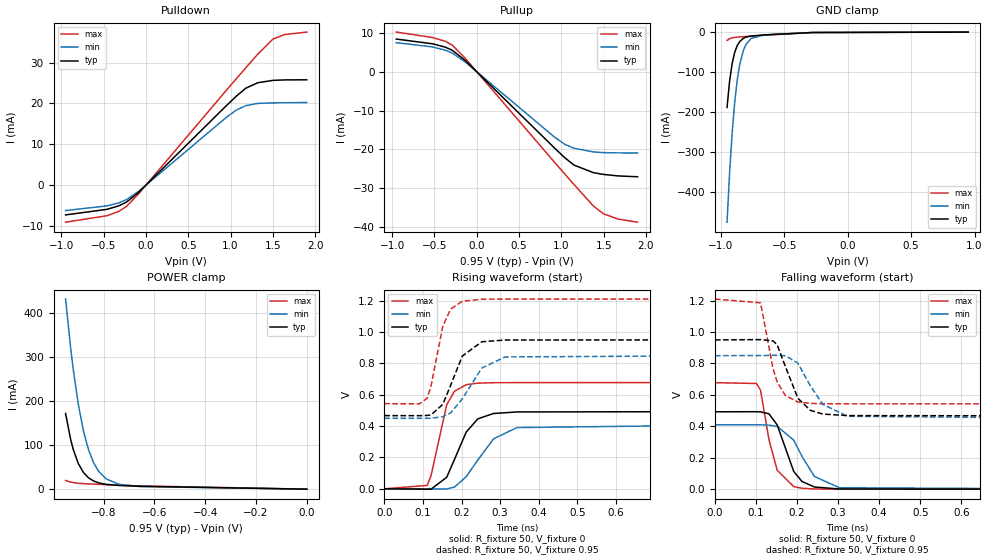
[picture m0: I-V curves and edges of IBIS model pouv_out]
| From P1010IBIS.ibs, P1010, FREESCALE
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[Model] pouv_out
Model_type 3-state
Enable Active-High
Polarity Non-Inverting
Vref=0.95
Vmeas=0.475
C_comp   911fF   857fF   939fF
[Temperature Range] 65   125   -40
[Voltage Range]   0.95   0.85   1.21
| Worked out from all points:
|   slope of the pulldown table from 0 to 0.142 V, typ, clamps not added: 48.1 ohm
|   slope of the pullup table from 0 to 0.142 V, typ, clamps not added: 46.3 ohm
|   GND clamp passes 1 mA (typ) near -0.27 V on its own axis
|   POWER clamp passes 1 mA (typ) near -0.31 V on its own axis
|   falling waveform, R_fixture 50, V_fixture 0: 20-80 % time 42.2ps typ, 54.1ps min, 32.3ps max; typ from 0.493 V to 0 V
|   falling waveform, R_fixture 50, V_fixture 0.95: 20-80 % time 43.8ps typ, 57ps min, 32.2ps max; typ from 0.95 V to 0.467 V
|   rising waveform, R_fixture 50, V_fixture 0: 20-80 % time 54.2ps typ, 73.6ps min, 36.9ps max; typ from 0 V to 0.493 V
|   rising waveform, R_fixture 50, V_fixture 0.95: 20-80 % time 47.9ps typ, 62.9ps min, 34.7ps max; typ from 0.467 V to 0.95 V
[Pullup]
-950mV    8.406mA    7.477mA    10.2mA
-520mV    7.186mA    6.375mA    8.797mA
-370mV    6.311mA    5.543mA    7.815mA
-290mV    5.536mA    4.814mA    6.861mA
-140mV    2.983mA    2.568mA    3.564mA
920mV     -19.65mA   -16.85mA   -23.32mA
1.04V     -22.13mA   -18.67mA   -26.31mA
1.15V     -24.04mA   -19.71mA   -29.04mA
1.38V     -25.99mA   -20.65mA   -34.59mA
1.5V      -26.44mA   -20.83mA   -36.59mA
1.67V     -26.82mA   -20.89mA   -37.93mA
1.9V      -27.04mA   -20.92mA   -38.73mA
[Pulldown]
-950mV    -7.316mA   -6.25mA    -9.099mA
-460mV    -5.947mA   -5.103mA   -7.51mA
-320mV    -5.081mA   -4.352mA   -6.442mA
-230mV    -4.174mA   -3.567mA   -5.229mA
-90mV     -1.842mA   -1.577mA   -2.209mA
950mV     19.45mA    16.59mA    23.22mA
1.07V     21.82mA    18.4mA     26.1mA
1.18V     23.73mA    19.45mA    28.73mA
1.32V     25.06mA    20mA       32.05mA
1.5V      25.64mA    20.13mA    35.76mA
1.64V     25.76mA    20.16mA    36.88mA
1.9V      25.78mA    20.22mA    37.47mA
[GND Clamp]
-950mV    -188.4mA   -475.2mA   -20.78mA
-930mV    -123.3mA   -352.8mA   -16.57mA
-910mV    -79.33mA   -253.5mA   -14.49mA
-890mV    -51.16mA   -176.8mA   -13.36mA
-870mV    -33.84mA   -120.5mA   -12.63mA
-850mV    -23.47mA   -80.94mA   -12.08mA
-820mV    -15.28mA   -44.59mA   -11.36mA
-800mV    -12.49mA   -30.55mA   -10.91mA
-760mV    -9.703mA   -15.9mA    -10.03mA
-660mV    -7.103mA   -6.762mA   -7.877mA
-280mV    -1.114mA   -1.008mA   -930.9uA
950mV     18.39uA    35.88uA    3.979uA
[POWER Clamp]
-950mV    172.2mA    432.7mA    19.91mA
-930mV    112.9mA    321.3mA    16.02mA
-920mV    90.76mA    273.4mA    14.89mA
-900mV    58.49mA    193.5mA    13.47mA
-880mV    38.27mA    133.3mA    12.62mA
-860mV    26.01mA    90.14mA    12mA
-840mV    18.7mA     60.44mA    11.48mA
-820mV    14.37mA    40.7mA     11mA
-790mV    10.89mA    23.34mA    10.31mA
-740mV    8.435mA    11.19mA    9.194mA
-660mV    6.585mA    6.025mA    7.434mA
0V        18.39uA    22.33uA    6.118uA
[Falling Waveform]
R_fixture=50
V_fixture=0
V_fixture_min=0
V_fixture_max=0
0s        492.6mV    409.4mV    677.8mV
101ps     493mV      409.5mV    672.7mV
111.1ps   491.8mV    409.6mV    629.2mV
131.3ps   480.2mV    407.7mV    318.2mV
151.5ps   409.3mV    399.6mV    120.5mV
191.9ps   112.5mV    312mV      16.13mV
212.1ps   48.69mV    208.2mV    5.84mV
242.4ps   13.72mV    80.52mV    1.29mV
303ps     1.124mV    9.222mV    56.62uV
1ns       9.644uV    12.28uV    8.706uV
[Falling Waveform]
R_fixture=50
V_fixture=0.95
V_fixture_min=0.85
V_fixture_max=1.21
0s        950mV      849.9mV    1.21V
111.1ps   951.9mV    850.4mV    1.186V
141.4ps   944.3mV    851.8mV    767.4mV
151.5ps   918.8mV    851.7mV    682.4mV
171.7ps   779.7mV    849.6mV    595.4mV
202ps     578.7mV    801.8mV    555mV
232.3ps   501.9mV    657.9mV    545.9mV
262.6ps   478mV      539.5mV    543.8mV
323.2ps   468.1mV    464mV      543.2mV
1ns       466.8mV    449.5mV    543.2mV
[Rising Waveform]
R_fixture=50
V_fixture=0
V_fixture_min=0
V_fixture_max=0
0s        8.078uV    12.27uV    6.354uV
111.1ps   -2.318mV   -976.2uV   21.52mV
121.2ps   -2.226mV   -1.544mV   84.13mV
161.6ps   73.15mV    -937.6uV   535.9mV
181.8ps   187.3mV    11.04mV    622.5mV
212.1ps   361.8mV    76.9mV     663.7mV
242.4ps   446.4mV    184.2mV    673.9mV
282.8ps   480.2mV    318.2mV    676.6mV
343.4ps   490.1mV    390.5mV    677.2mV
1ns       492.6mV    409.4mV    677.3mV
[Rising Waveform]
R_fixture=50
V_fixture=0.95
V_fixture_min=0.85
V_fixture_max=1.21
0s        466.7mV    449.5mV    542.9mV
90.91ps   466.3mV    449.4mV    541.7mV
111.1ps   467.8mV    449.6mV    577.3mV
121.2ps   471.2mV    450.3mV    657.1mV
151.5ps   538.4mV    459.7mV    1.036V
171.7ps   659.2mV    483.4mV    1.146V
202ps     846.5mV    573.4mV    1.196V
252.5ps   937.7mV    770.4mV    1.209V
313.1ps   948.8mV    841mV      1.21V
1ns       950mV      849.9mV    1.21V
[Ramp]
R_load=50
dV/dt_r   2.956E-1/5.367E-11   2.456E-1/7.332E-11   4.064E-1/3.625E-11
dV/dt_f   2.899E-1/4.331E-11   2.402E-1/5.620E-11   4.001E-1/3.171E-11
| End [Model] pouv_out
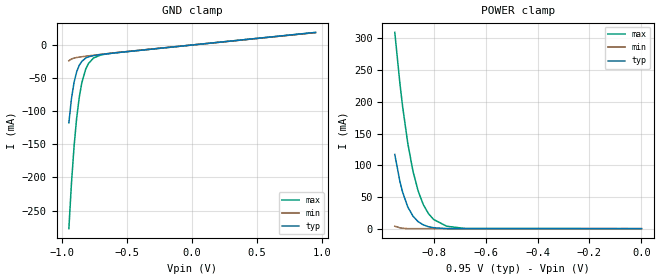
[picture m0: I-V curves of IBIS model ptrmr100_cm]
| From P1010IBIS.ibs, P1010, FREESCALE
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[Model] ptrmr100_cm
Model_type Input
Polarity Non-Inverting
Vinh=0.8
Vinl=0.2
C_comp   861f   858f   865f
[Temperature Range] 65   125   -40
[Voltage Range]   0.95   0.85   1.21
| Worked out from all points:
|   GND clamp passes 1 mA (typ) near -0.05 V on its own axis
|   POWER clamp passes 1 mA (typ) near -0.79 V on its own axis
[GND Clamp]
-950mV    -117.6mA   -23.88mA   -277.3mA
-930mV    -81.21mA   -21.29mA   -209mA
-910mV    -56.51mA   -19.89mA   -153.6mA
-890mV    -40.61mA   -19.02mA   -110.7mA
-870mV    -30.75mA   -18.37mA   -79.18mA
-850mV    -24.75mA   -17.81mA   -56.97mA
-820mV    -19.85mA   -17.05mA   -36.4mA
-800mV    -18.06mA   -16.55mA   -28.36mA
-760mV    -16.04mA   -15.59mA   -19.74mA
-700mV    -14.34mA   -14.19mA   -14.91mA
-600mV    -12.13mA   -11.97mA   -11.98mA
950mV     18.9mA     18.65mA    18.7mA
[POWER Clamp]
-950mV    117mA      3.854mA    309.6mA
-930mV    73.8mA     1.336mA    228mA
-920mV    57.68mA    678.8uA    193.1mA
-900mV    34.27mA    0A         134.7mA
-880mV    19.71mA    0A         90.75mA
-860mV    10.99mA    0A         59.3mA
-840mV    5.915mA    0A         37.75mA
-820mV    3.026mA    0A         23.52mA
-800mV    1.419mA    0A         14.37mA
-750mV    0A         0A         3.804mA
-680mV    0A         0A         301.8uA
0V        0A         0A         0A
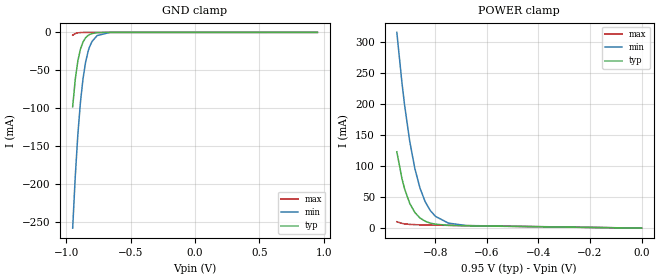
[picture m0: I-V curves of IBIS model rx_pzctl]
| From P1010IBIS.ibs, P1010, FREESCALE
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[Model] rx_pzctl
Model_type Input
Vinh=0.8
Vinl=0.2
C_comp   777.9fF   774fF   777.9fF
[Model Spec]
[Temperature Range] 65   125   -40
[Voltage Range]   0.95   0.85   1.21
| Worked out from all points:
|   GND clamp passes 1 mA (typ) near -0.78 V on its own axis
|   POWER clamp passes 1 mA (typ) near -0.20 V on its own axis
[GND Clamp]
-950mV    -97.94mA   -257.8mA   -3.716mA
-930mV    -61.95mA   -189.9mA   -1.592mA
-910mV    -37.66mA   -134.9mA   -635.2uA
-890mV    -22.19mA   -92.43mA   -240.6uA
-870mV    -12.76mA   -61.31mA   -77.01uA
-850mV    -7.163mA   -39.51mA   0A
-830mV    -3.946mA   -24.87mA   0A
-820mV    -2.931mA   -19.61mA   0A
-800mV    -1.573mA   -12mA      0A
-760mV    -397uA     -4.205mA   0A
-660mV    0A         -40.52uA   0A
950mV     0A         0A         0A
[POWER Clamp]
-950mV    122.8mA    314.9mA    10.28mA
-930mV    79.52mA    233.3mA    7.619mA
-920mV    63.35mA    198.3mA    6.886mA
-900mV    39.84mA    139.8mA    6.034mA
-880mV    25.16mA    95.75mA    5.598mA
-860mV    16.32mA    64.2mA     5.335mA
-840mV    11.12mA    42.55mA    5.144mA
-820mV    8.094mA    28.2mA     4.982mA
-800mV    6.352mA    18.94mA    4.833mA
-750mV    4.532mA    8.087mA    4.476mA
-680mV    3.753mA    4.17mA     3.987mA
0V        69.52nA    46.88nA    142.3nA
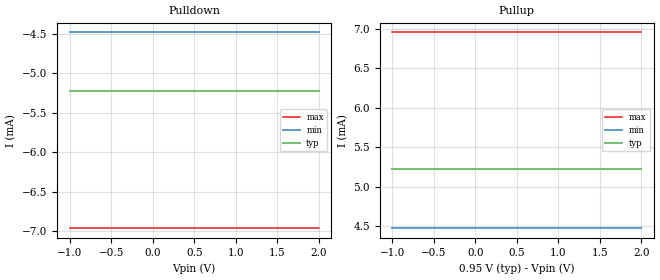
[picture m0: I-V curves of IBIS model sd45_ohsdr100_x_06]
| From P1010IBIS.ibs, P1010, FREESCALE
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[Model] sd45_ohsdr100_x_06
Model_type 3-state
Enable Active-High
Polarity Non-Inverting
|   TYP   MIN   MAX
C_comp   0.00pF   0.00pF   0.00pF
[Model Spec]
Vmeas   0.475   0.425   0.605
[Temperature Range] 65   125   -40
[Voltage Range]   0.95   0.85   1.21
[Pullup]
|   Vout(V)   TYP   WCS   BCS
-1V       5.23mA     4.478mA    6.957mA
2V        5.23mA     4.478mA    6.957mA
[Pulldown]
|   Vout(V)   TYP   WCS   BCS
-1V       -5.229mA   -4.48mA    -6.964mA
2V        -5.229mA   -4.48mA    -6.964mA
[GND Clamp]
|   Vout(V)   TYP   WCS   BCS
-1V       0A         0A         0A
1V        0A         0A         0A
[POWER Clamp]
|   Vout(V)   TYP   WCS   BCS
-1V       0A         0A         0A
0V        0A         0A         0A
[Ramp]
R_load=50
dV/dt_r  2.9887e-01/6.4040e-11  2.6861e-01/6.5155e-11  3.8214e-01/6.5744e-11
dV/dt_f  2.9887e-01/6.6355e-11  2.6861e-01/6.7761e-11  3.8218e-01/6.7348e-11
| End [Model] sd45_ohsdr100_x_06
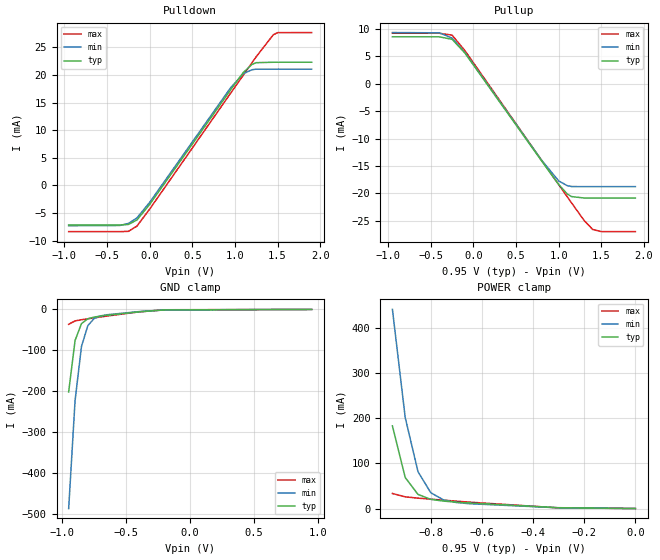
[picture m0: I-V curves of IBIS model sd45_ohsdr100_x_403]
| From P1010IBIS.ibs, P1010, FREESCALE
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[Model] sd45_ohsdr100_x_403
Model_type 3-state
Enable Active-High
Polarity Non-Inverting
|   TYP   MIN   MAX
C_comp   1.60pF   1.60pF   1.67pF
[Model Spec]
Vmeas   0.475   0.425   0.605
[Voltage Range]   0.95   0.85   1.21
[Temperature Range] 65   125   -40
[Driver Schedule]
sd45_ohsdr100_x_40   0ps   NA   0ps   NA
sd45_ohsdr100_x_43   800ps   NA   800ps   NA
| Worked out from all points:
|   slope of the pulldown table from 0 to 0.142 V, typ, clamps not added: 45.7 ohm
|   slope of the pullup table from 0 to 0.142 V, typ, clamps not added: 45.5 ohm
|   GND clamp passes 1 mA (typ) near -0.19 V on its own axis
|   POWER clamp passes 1 mA (typ) near -0.25 V on its own axis
[Pullup]
|   Vout(V)   TYP   WCS   BCS
-950mV    8.533mA    9.319mA    9.19mA
-400mV    8.533mA    9.264mA    9.19mA
-250mV    8.088mA    8.312mA    8.847mA
-100mV    5.595mA    5.69mA     6.03mA
800mV     -14.07mA   -13.94mA   -13.96mA
1V        -18.36mA   -17.7mA    -18.37mA
1.1V      -20.07mA   -18.57mA   -20.58mA
1.15V     -20.56mA   -18.73mA   -21.68mA
1.3V      -20.83mA   -18.75mA   -24.94mA
1.4V      -20.83mA   -18.75mA   -26.56mA
1.5V      -20.83mA   -18.75mA   -26.95mA
1.9V      -20.83mA   -18.75mA   -26.95mA
[Pulldown]
|   Vout(V)   TYP   WCS   BCS
-950mV    -7.174mA   -7.31mA    -8.383mA
-350mV    -7.174mA   -7.267mA   -8.383mA
-250mV    -7.08mA    -6.904mA   -8.331mA
-150mV    -6.282mA   -5.916mA   -7.391mA
0V        -3.456mA   -3.082mA   -4.305mA
950mV     17.31mA    17.69mA    16.7mA
1.1V      20.47mA    20.23mA    20mA
1.2V      21.9mA     20.94mA    22.2mA
1.25V     22.22mA    21.05mA    23.3mA
1.45V     22.3mA     21.05mA    27.27mA
1.5V      22.3mA     21.05mA    27.66mA
1.9V      22.3mA     21.05mA    27.68mA
[GND Clamp]
|   Vout(V)   TYP   WCS   BCS
-950mV    -201.6mA   -486.5mA   -36.16mA
-900mV    -75.75mA   -222.9mA   -28.05mA
-850mV    -34.66mA   -90.59mA   -25.11mA
-800mV    -22.71mA   -39.37mA   -22.78mA
-750mV    -18.57mA   -21.91mA   -20.52mA
-700mV    -16.25mA   -15.71mA   -18.29mA
-650mV    -14.32mA   -12.88mA   -16.07mA
-400mV    -5.858mA   -5.175mA   -5.911mA
-200mV    -1.108mA   -1.072mA   -756.7uA
950mV     70.01uA    122.9uA    16.34uA
[POWER Clamp]
|   Vout(V)   TYP   WCS   BCS
-950mV    183.5mA    442.2mA    33.42mA
-900mV    68.86mA    202.2mA    25.88mA
-850mV    31.34mA    81.75mA    23.04mA
-800mV    20.35mA    35.06mA    20.76mA
-750mV    16.45mA    19.08mA    18.55mA
-700mV    14.21mA    13.35mA    16.36mA
-650mV    12.35mA    10.71mA    14.18mA
-300mV    1.805mA    1.559mA    1.409mA
0V        0A         0A         0A
[Ramp]
R_load=50.00
dV/dt_r  1.9939e-01/6.4174e-11  1.7268e-01/6.5633e-11  2.6621e-01/6.5297e-11
dV/dt_f  1.9939e-01/6.5911e-11  1.7267e-01/6.8201e-11  2.6623e-01/6.6334e-11
| End [Model] sd45_ohsdr100_x_403
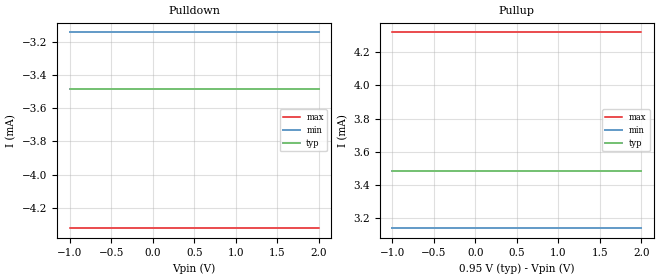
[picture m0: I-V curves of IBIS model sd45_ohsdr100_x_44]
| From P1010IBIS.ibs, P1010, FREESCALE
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[Model] sd45_ohsdr100_x_44
Model_type 3-state
Enable Active-High
Polarity Non-Inverting
|   TYP   MIN   MAX
C_comp   0.00pF   0.00pF   0.00pF
[Model Spec]
Vmeas   0.475   0.425   0.605
[Temperature Range] 65   125   -40
[Voltage Range]   0.95   0.85   1.21
[Pullup]
|   Vout(V)   TYP   WCS   BCS
-1V       3.486mA    3.14mA     4.319mA
2V        3.486mA    3.14mA     4.319mA
[Pulldown]
|   Vout(V)   TYP   WCS   BCS
-1V       -3.486mA   -3.142mA   -4.323mA
2V        -3.486mA   -3.142mA   -4.323mA
[GND Clamp]
|   Vout(V)   TYP   WCS   BCS
-1V       0A         0A         0A
1V        0A         0A         0A
[POWER Clamp]
|   Vout(V)   TYP   WCS   BCS
-1V       0A         0A         0A
0V        0A         0A         0A
[Ramp]
R_load=50
dV/dt_r  1.9939e-01/6.4174e-11  1.7268e-01/6.5633e-11  2.6621e-01/6.5297e-11
dV/dt_f  1.9939e-01/6.5911e-11  1.7267e-01/6.8201e-11  2.6623e-01/6.6334e-11
| End [Model] sd45_ohsdr100_x_44
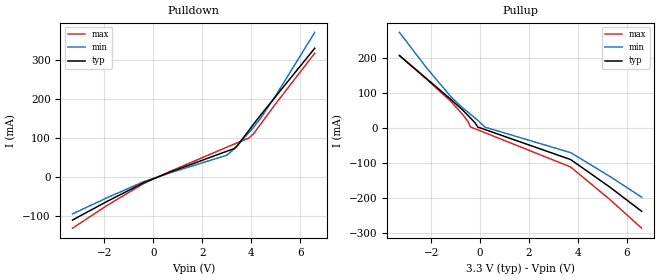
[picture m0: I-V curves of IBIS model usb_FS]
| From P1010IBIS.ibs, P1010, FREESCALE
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[Model] usb_FS
Model_type   I/O
Vinl = 0.8
Vinh = 2
Vmeas = 0.95
Cref = 5E-11
Rref = 50
Vref = 0
| C_comp   typ   min   max
C_comp  9.11p   8.97p   9.24p
| variable   typ   min   max
[Temperature Range]   27.0   -40.0   125.0
| variable   typ   min   max
[Pullup Reference]   3.300V   3.00V   3.6V
| variable   typ   min   max
[Pulldown Reference]   0.000V   0.000V   0.000V
| variable   typ   min   max
[POWER_Clamp_Reference]   3.300V   3.0V   3.60V
| variable   typ   min   max
[GND_Clamp_Reference]   0.000V   0.000V   0.000V
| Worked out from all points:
|   slope of the pulldown table from 0 to 0.495 V, typ, clamps not added: 40.3 ohm
|   slope of the pullup table from 0 to 0.495 V, typ, clamps not added: 41.6 ohm
[Pulldown]
|Voltage   I(typ)   I(min)   I(max)
-3.3V     -110mA     -94.26mA   -130.8mA
-1.9V     -62.61mA   -53.2mA    -73.19mA
-400mV    -14.67mA   -11.84mA   -16.47mA
700mV     13.22mA    11.37mA    14.87mA
3V        66.17mA    55.93mA    76.59mA
3.3V      72.85mA    71.79mA    84.34mA
3.4V      77.81mA    78.37mA    86.91mA
3.9V      119mA      113.6mA    99.99mA
4.1V      135.8mA    127.4mA    111.1mA
4.4V      159.9mA    151.9mA    136.9mA
5V        206.6mA    208.5mA    187.8mA
6.6V      330.4mA    371mA      317.7mA
[Pullup]
|Voltage   I(typ)   I(min)   I(max)
-3.3V     206.2mA    271.9mA    205.5mA
-2.2V     140.9mA    171.8mA    139.2mA
-1.2V     81.43mA    89.19mA    75.68mA
-700mV    50mA       56.08mA    36.82mA
-500mV    35.94mA    45.08mA    18.55mA
-400mV    28.53mA    39.38mA    2.963mA
-200mV    13.96mA    27.66mA    -2.595mA
-100mV    2.572mA    21.77mA    -5.373mA
200mV     -4.636mA   2.225mA    -13.7mA
3.7V      -89.96mA   -70.28mA   -111.2mA
5.3V      -168.3mA   -137.8mA   -203.5mA
6.6V      -237.1mA   -196.9mA   -285mA
[GND_clamp]
0V        0A         0A         0A
100mV     0A         0A         0A
[POWER_clamp]
0V        0A         0A         0A
100mV     0A         0A         0A
[Ramp]
| variable   typ   min   max
dV/dt_r   1.95/4.283n   2.11/3.501n   1.75/5.180n
dV/dt_f   1.95/4.630n   2.11/4.002n   1.75/5.416n
| End [Model] usb_FS
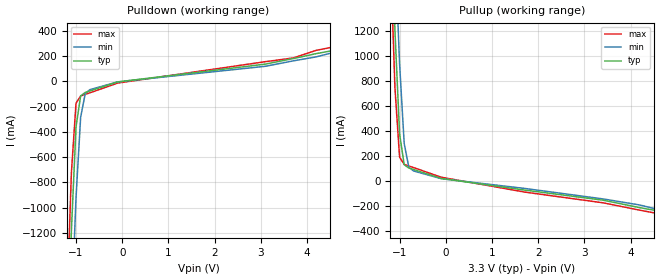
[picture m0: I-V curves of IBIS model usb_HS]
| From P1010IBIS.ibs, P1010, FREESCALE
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[Model] usb_HS
Model_type   I/O
Vinl = 10m
Vinh = 400m
Vmeas = 150m
Cref = 5E-12
Rref = 50
| C_comp   typ   min   max
C_comp  7.19p   6.53p   7.96p
| variable   typ   min   max
[Temperature Range]   27.0   -40.0   125.0
| variable   typ   min   max
[Pullup Reference]   3.300V   3.00V   3.6V
| variable   typ   min   max
[Pulldown Reference]   0.000V   0.000V   0.000V
| variable   typ   min   max
[POWER_Clamp_Reference]   3.300V   3.0V   3.60V
| variable   typ   min   max
[GND_Clamp_Reference]   0.000V   0.000V   0.000V
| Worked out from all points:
|   slope of the pulldown table from 0 to 0.495 V, typ, clamps not added: 22.5 ohm
|   slope of the pullup table from 0 to 0.495 V, typ, clamps not added: 22.5 ohm
[Pulldown]
|Voltage   I(typ)   I(min)   I(max)
-3.3V     -25.44A    -23.8A     -26.86A
-1.2V     -2.217A    -2.794A    -1.795A
-1.1V     -1.182A    -1.85A     -724mA
-1V       -360.4mA   -920.4mA   -173.3mA
-900mV    -114.5mA   -284mA     -115.6mA
-800mV    -87.65mA   -96.06mA   -102.9mA
-700mV    -76.37mA   -65.76mA   -90.71mA
-100mV    -4.452mA   -3.942mA   -13.7mA
3.1V      136.7mA    119.6mA    156mA
3.7V      180.6mA    162.3mA    185.5mA
4.2V      220mA      194.3mA    245.9mA
6.6V      381.4mA    416.5mA    417.8mA
[Pullup]
|Voltage   I(typ)   I(min)   I(max)
-3.3V     25.46A     23.82A     26.88A
-1.2V     2.235A     2.811A     1.814A
-1.1V     1.2A       1.867A     743.6mA
-1V       378.7mA    937.4mA    192.9mA
-900mV    132.9mA    301.1mA    135.2mA
-800mV    106mA      113.3mA    122.4mA
-700mV    94.76mA    82.99mA    110.2mA
-100mV    22.82mA    21.15mA    32.78mA
1.7V      -69.5mA    -56.47mA   -85.53mA
3.4V      -150.7mA   -140.4mA   -171.4mA
4.2V      -210.5mA   -189.2mA   -230.6mA
6.6V      -366.3mA   -407.6mA   -396.8mA
[GND_clamp]
0V        0A         0A         0A
100mV     0A         0A         0A
[POWER_clamp]
0V        0A         0A         0A
100mV     0A         0A         0A
[Ramp]
| variable   typ   min   max
dV/dt_r   0.24/880.963p   0.22/532.484p   0.26/1.108n
dV/dt_f   0.24/431.881p   0.22/372.480p   0.26/513.903p
| End [Model] usb_HS
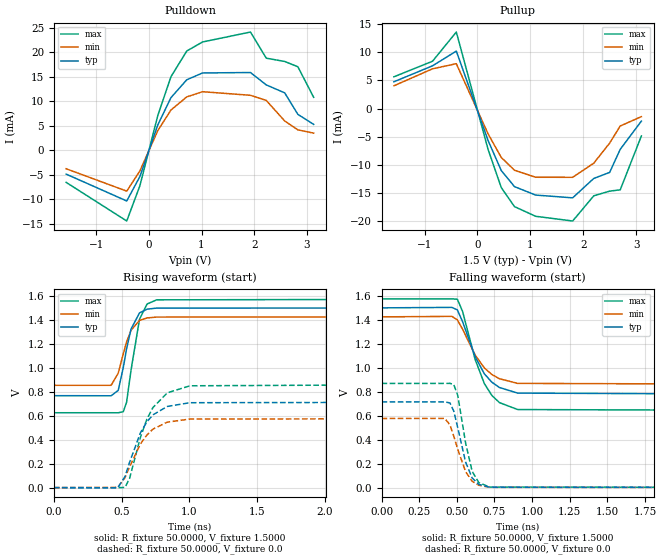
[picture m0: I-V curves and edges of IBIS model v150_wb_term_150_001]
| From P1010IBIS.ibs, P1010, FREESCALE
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[Model] v150_wb_term_150_001
|   Model v150_wb_term_150_001
| This model was characterised for following simulation conditions:
| External (pad) voltage:
|   - Typ: 1.5V,   - Min: 1.425V,   - Max: 1.575V
| Library cells for typ/min/max conditions are connected as defined below:
|  chip_pad - External Pad
|  ipp_do - Core Input
|  ipp_obe - Output Buffer Enable
|  esd_boost - vdd_io
|  gnd_io - gnd_io
|  vdd_d - vdd_d
|  vdd_io - vdd_io
|  vipp_dse_0 - gnd_io
|  vipp_dse_1 - vdd_d vdd_d gnd_io
|  vipp_dse_2 - vdd_d gnd_io gnd_io
|  vipp_dse_3 - gnd_io
|  vipp_dse_4 - gnd_io
|  vipp_dse_5 - vdd_d vdd_d gnd_io
|  vipp_dse_6 - vdd_d gnd_io vdd_d
|  vipp_dse_7 - gnd_io gnd_io vdd_d
|  vsel[0] - gnd_io
|  vsel[1] - vdd_d
|  vtermsel_0 - gnd_io
|  vtermsel_1 - gnd_io
|  vtermsel_2 - vdd_d
| All other pins connected to ground
Model_type I/O
Polarity   Non-Inverting
Enable   Active-High
Vinl =   0.5750V
Vinh =   0.9250V
Vmeas =  0.7500V
Cref =   0.0F
Rref =   50.0000
Vref =   0.7500V
C_comp   2.2026pF   1.9235pF   2.5884pF
[Receiver Thresholds]
Vth   =  0.750V
Vinh_ac  =  0.175V
Vinh_dc  =  0.100V
Vinl_ac  = -0.175V
Vinl_dc  = -0.100V
[Temperature Range]   65.0000   0.1250k   -40.0000
[Voltage Range]   1.5000V   1.4250V   1.5750V
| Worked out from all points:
|   slope of the pulldown table from 0 to 0.225 V, typ, clamps not added: 35.6 ohm
|   slope of the pullup table from 0 to 0.225 V, typ, clamps not added: 36 ohm
|   rising waveform, R_fixture 50.0000, V_fixture 1.5000: 20-80 % time 80.4ps typ, 90.1ps min, 77.1ps max; typ from 0.768 V to 1.5 V
|   rising waveform, R_fixture 50.0000, V_fixture 0.0: 20-80 % time 162ps typ, 168ps min, 166ps max; typ from 0 V to 0.716 V
|   falling waveform, R_fixture 50.0000, V_fixture 1.5000: 20-80 % time 159ps typ, 167ps min, 148ps max; typ from 1.5 V to 0.768 V
|   falling waveform, R_fixture 50.0000, V_fixture 0.0: 20-80 % time 84.1ps typ, 94.3ps min, 75.4ps max; typ from 0.716 V to 0 V
[Pulldown]
|Voltage   I(typ)   I(min)   I(max)
-1.57V    -4.914mA   -3.818mA   -6.602mA
-420mV    -10.4mA    -8.389mA   -14.49mA
-170mV    -5.399mA   -4.253mA   -7.279mA
170mV     5.137mA    3.982mA    7.064mA
420mV     10.71mA    8.187mA    14.99mA
720mV     14.36mA    10.86mA    20.23mA
1.02V     15.75mA    11.92mA    22.08mA
1.93V     15.84mA    11.19mA    24.11mA
2.23V     13.31mA    10.14mA    18.77mA
2.58V     11.69mA    5.94mA     18.1mA
2.83V     7.3mA      4.13mA     17.02mA
3.13V     5.25mA     3.46mA     10.78mA
[Pullup]
|Voltage   I(typ)   I(min)   I(max)
-1.58V    4.77mA     4.06mA     5.65mA
-850mV    7.598mA    7.066mA    8.413mA
-400mV    10.21mA    7.977mA    13.59mA
200mV     -5.632mA   -4.457mA   -7.203mA
450mV     -10.97mA   -8.649mA   -13.99mA
700mV     -13.82mA   -10.92mA   -17.37mA
1.1V      -15.32mA   -12.16mA   -19.08mA
1.8V      -15.81mA   -12.17mA   -19.92mA
2.2V      -12.37mA   -9.661mA   -15.45mA
2.5V      -11.3mA    -6.103mA   -14.62mA
2.7V      -7.204mA   -3.069mA   -14.39mA
3.1V      -2.206mA   -1.416mA   -4.843mA
[Ramp]
| variable   typ   min   max
dV/dt_r  0.4296/0.1623n   0.3469/0.1685n   0.5223/0.1664n
dV/dt_f  0.4395/0.1589n   0.3427/0.1667n   0.5638/0.1475n
R_load = 50.0000
[Rising Waveform]
R_fixture= 50.0000
V_fixture= 1.5000
V_fixture_min= 1.4250
V_fixture_max= 1.5750
|time   V(typ)   V(min)   V(max)
0s        767.5mV    853.8mV    624.9mV
422.9ps   766.6mV    853.9mV    624.9mV
475.2ps   811.8mV    955.6mV    624.7mV
512.3ps   1.002V     1.116V     633.6mV
536.5ps   1.157V     1.215V     711.5mV
569.9ps   1.324V     1.314V     981.7mV
632.2ps   1.458V     1.395V     1.405V
687.9ps   1.489V     1.416V     1.532V
758.8ps   1.498V     1.423V     1.567V
5ns       1.5V       1.425V     1.575V
[Rising Waveform]
R_fixture= 50.0000
V_fixture= 0.0
V_fixture_min= 0.0
V_fixture_max= 0.0
|time   V(typ)   V(min)   V(max)
0s        7.324uV    39.66uV    145.1nV
471.2ps   -1.643mV   2.083mV    195.1uV
525.2ps   92.5mV     84.61mV    1.477mV
558.8ps   211.3mV    173.3mV    77.35mV
638.4ps   456mV      363.6mV    418.5mV
686.5ps   549.4mV    439.5mV    571.3mV
731ps     607.3mV    488.1mV    668.2mV
837.4ps   677.6mV    546.8mV    791.1mV
1.004ns   708.6mV    572.3mV    849.8mV
5ns       716.1mV    578.2mV    870.5mV
[Falling Waveform]
R_fixture= 50.0000
V_fixture= 1.5000
V_fixture_min= 1.4250
V_fixture_max= 1.5750
|time   V(typ)   V(min)   V(max)
0s        1.5V       1.425V     1.575V
466.9ps   1.504V     1.429V     1.575V
503.3ps   1.483V     1.4V       1.572V
538.1ps   1.385V     1.322V     1.47V
621.4ps   1.093V     1.107V     1.07V
683ps     949.7mV    998.9mV    867.9mV
732.8ps   880.2mV    944.3mV    769.6mV
782.9ps   836.2mV    909.3mV    710.4mV
903.8ps   789.6mV    870.6mV    652.6mV
5ns       767.5mV    853.8mV    635.4mV
[Falling Waveform]
R_fixture= 50.0000
V_fixture= 0.0
V_fixture_min= 0.0
V_fixture_max= 0.0
|time   V(typ)   V(min)   V(max)
0s        716.1mV    578.2mV    870.5mV
419.9ps   716.4mV    578.4mV    870.5mV
454.3ps   707.4mV    524.5mV    870.9mV
478.9ps   641.5mV    433.7mV    862.2mV
505.9ps   502.1mV    321.6mV    771mV
557.8ps   216.3mV    135.4mV    376.2mV
601.5ps   82.45mV    55.39mV    137.9mV
645.9ps   28.67mV    21.31mV    43.71mV
716.5ps   5.495mV    4.642mV    6.886mV
5ns       7.524uV    40.13uV    220.6nV
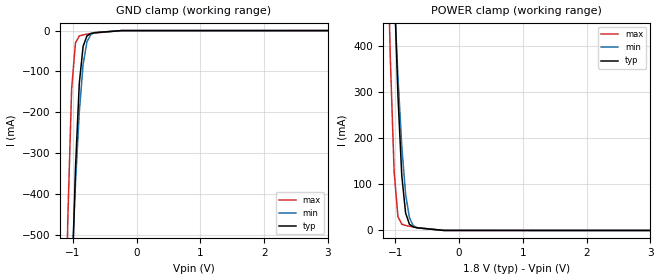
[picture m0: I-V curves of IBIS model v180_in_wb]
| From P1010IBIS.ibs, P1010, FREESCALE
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[Model] v180_in_wb
|   Model v180_in_wb
| This model has derived from v180_wb
| Only applicable curves and parameters are copied
Model_type Input
Polarity   Non-Inverting
Enable   Active-High
Vinl =   0.5400V
Vinh =   1.2600V
C_comp   2.1221pF   1.9600pF   2.4667pF
[Temperature Range]   85.0000   0.1250k   -40.0000
[Voltage Range]   1.8000V   1.6200V   1.9800V
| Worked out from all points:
|   GND clamp passes 1 mA (typ) near -0.40 V on its own axis
|   POWER clamp passes 1 mA (typ) near -0.37 V on its own axis
[GND_clamp]
|Voltage   I(typ)   I(min)   I(max)
-1.98V    -8.37A     -5.087A    -9.647A
-1.14V    -1.459A    -1.082A    -930.9mA
-1.08V    -1.036A    -828.3mA   -462.6mA
-1.02V    -653.4mA   -590.2mA   -143.2mA
-960mV    -338mA     -376mA     -30.24mA
-900mV    -129.6mA   -200.5mA   -13.2mA
-840mV    -38.64mA   -82.98mA   -10.47mA
-780mV    -13.16mA   -27.75mA   -8.896mA
-720mV    -7.156mA   -9.942mA   -7.424mA
-660mV    -5.182mA   -5.042mA   -5.995mA
-240mV    -56.29uA   -39.98uA   -23.22uA
3.9V      0A         0A         0A
[POWER_clamp]
|Voltage   I(typ)   I(min)   I(max)
-1.92V    6.087A     4.039A     6.601A
-1.14V    1.168A     928.8mA    722.7mA
-1.08V    840.5mA    715.6mA    374.8mA
-1.02V    542mA      514.8mA    127.3mA
-960mV    291.6mA    333.1mA    29.94mA
-900mV    119mA      182.4mA    13.62mA
-840mV    37.87mA    78.7mA     10.87mA
-780mV    13.54mA    27.69mA    9.257mA
-720mV    7.641mA    10.53mA    7.748mA
-660mV    5.688mA    5.717mA    6.285mA
-240mV    130.6uA    144.5uA    23.85uA
3.96V     0A         0A         0A
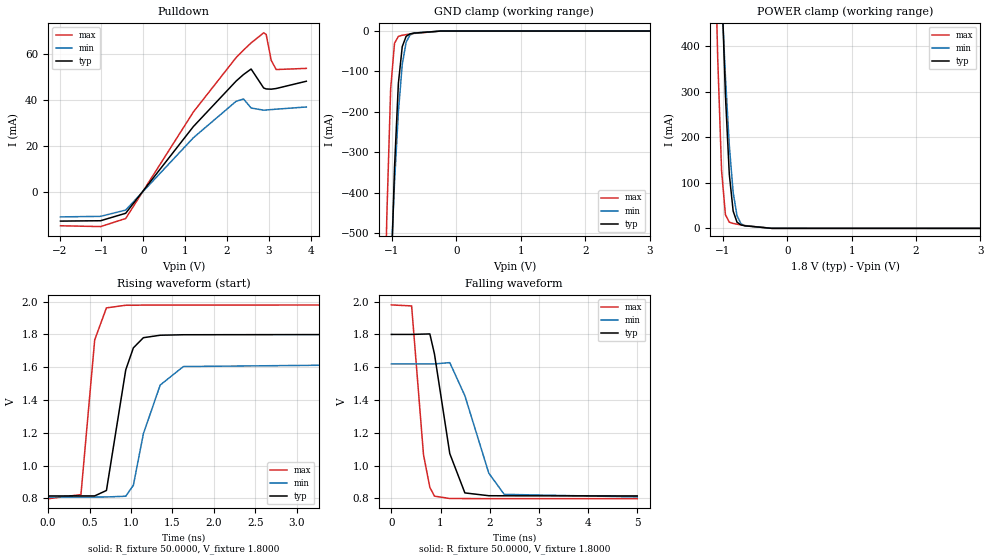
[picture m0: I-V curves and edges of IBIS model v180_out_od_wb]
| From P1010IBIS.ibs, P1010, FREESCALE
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[Model] v180_out_od_wb
|   Model v180_out_od_wb
| This model has derived from v180_wb
| Only applicable curves and parameters are copied
Model_type Open_drain
Polarity   Non-Inverting
Enable   Active-High
Vmeas =  0.9000V
Cref =   0.0F
Rref =   50.0000
Vref =   0.9000V
C_comp   2.1221pF   1.9600pF   2.4667pF
[Temperature Range]   85.0000   0.1250k   -40.0000
[Voltage Range]   1.8000V   1.6200V   1.9800V
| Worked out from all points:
|   slope of the pulldown table from 0 to 0.27 V, typ, clamps not added: 40.4 ohm
|   GND clamp passes 1 mA (typ) near -0.40 V on its own axis
|   POWER clamp passes 1 mA (typ) near -0.37 V on its own axis
|   rising waveform, R_fixture 50.0000, V_fixture 1.8000: 20-80 % time 186ps typ, 252ps min, 118ps max; typ from 0.814 V to 1.8 V
|   falling waveform, R_fixture 50.0000, V_fixture 1.8000: 20-80 % time 320ps typ, 504ps min, 177ps max; typ from 1.8 V to 0.814 V
[Pulldown]
|Voltage   I(typ)   I(min)   I(max)
-1.98V    -12.66mA   -10.83mA   -14.68mA
-1.02V    -12.5mA    -10.6mA    -15.04mA
-420mV    -9.259mA   -7.874mA   -11.53mA
1.2V      28.39mA    23.53mA    34.72mA
2.22V     48.08mA    39.31mA    58.26mA
2.4V      50.97mA    40.32mA    61.59mA
2.58V     53.33mA    36.41mA    64.65mA
2.88V     45.1mA     35.47mA    69.04mA
2.94V     44.69mA    35.54mA    68.34mA
3.06V     44.58mA    35.73mA    57.1mA
3.18V     44.88mA    35.91mA    53.1mA
3.9V      48.03mA    36.86mA    53.61mA
[GND_clamp]
|Voltage   I(typ)   I(min)   I(max)
-1.98V    -8.37A     -5.087A    -9.647A
-1.14V    -1.459A    -1.082A    -930.9mA
-1.08V    -1.036A    -828.3mA   -462.6mA
-1.02V    -653.4mA   -590.2mA   -143.2mA
-960mV    -338mA     -376mA     -30.24mA
-900mV    -129.6mA   -200.5mA   -13.2mA
-840mV    -38.64mA   -82.98mA   -10.47mA
-780mV    -13.16mA   -27.75mA   -8.896mA
-720mV    -7.156mA   -9.942mA   -7.424mA
-660mV    -5.182mA   -5.042mA   -5.995mA
-240mV    -56.29uA   -39.98uA   -23.22uA
3.9V      0A         0A         0A
[POWER_clamp]
|Voltage   I(typ)   I(min)   I(max)
-1.92V    6.087A     4.039A     6.601A
-1.14V    1.168A     928.8mA    722.7mA
-1.08V    840.5mA    715.6mA    374.8mA
-1.02V    542mA      514.8mA    127.3mA
-960mV    291.6mA    333.1mA    29.94mA
-900mV    119mA      182.4mA    13.62mA
-840mV    37.87mA    78.7mA     10.87mA
-780mV    13.54mA    27.69mA    9.257mA
-720mV    7.641mA    10.53mA    7.748mA
-660mV    5.688mA    5.717mA    6.285mA
-240mV    130.6uA    144.5uA    23.85uA
3.96V     0A         0A         0A
[Ramp]
| variable   typ   min   max
dV/dt_r  0.5852/0.3523n   0.4766/0.5910n   0.7103/0.1825n
dV/dt_f  0.5912/0.3203n   0.4869/0.5037n   0.7093/0.1774n
R_load = 50.0000
[Rising Waveform]
R_fixture= 50.0000
V_fixture= 1.8000
V_fixture_min= 1.6200
V_fixture_max= 1.9800
|time   V(typ)   V(min)   V(max)
0s        814.3mV    807.8mV    797.5mV
396ps     814.4mV    807.8mV    822.5mV
562.2ps   814.6mV    807.9mV    1.767V
703.9ps   847.6mV    808.1mV    1.962V
937.1ps   1.584V     812.5mV    1.978V
1.029ns   1.718V     879.5mV    1.978V
1.15ns    1.78V      1.194V     1.979V
1.353ns   1.795V     1.491V     1.979V
1.633ns   1.798V     1.604V     1.979V
5ns       1.8V       1.62V      1.98V
[Falling Waveform]
R_fixture= 50.0000
V_fixture= 1.8000
V_fixture_min= 1.6200
V_fixture_max= 1.9800
|time   V(typ)   V(min)   V(max)
0s        1.8V       1.62V      1.98V
412.1ps   1.8V       1.62V      1.974V
653.6ps   1.802V     1.62V      1.066V
782.7ps   1.803V     1.62V      866.8mV
876.4ps   1.681V     1.62V      813.2mV
1.188ns   1.073V     1.628V     798.8mV
1.495ns   832.9mV    1.426V     798.3mV
1.981ns   815.8mV    953.9mV    797.9mV
2.294ns   815.3mV    824.2mV    797.7mV
5ns       814.5mV    808.3mV    797.6mV
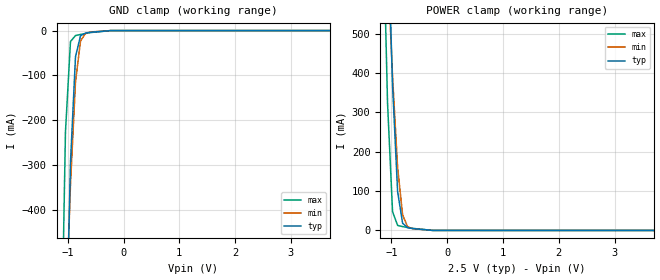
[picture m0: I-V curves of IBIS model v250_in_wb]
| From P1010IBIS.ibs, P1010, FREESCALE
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[Model] v250_in_wb
|   Model v250_in_wb
| This model has derived from v250_wb
| Only applicable curves and parameters are copied
Model_type Input
Polarity   Non-Inverting
Enable   Active-High
Vinl =   0.7500V
Vinh =   1.7500V
C_comp   2.1221pF   1.9600pF   2.4667pF
[Temperature Range]   85.0000   0.1250k   -40.0000
[Voltage Range]   2.5000V   2.2500V   2.7500V
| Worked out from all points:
|   GND clamp passes 1 mA (typ) near -0.40 V on its own axis
|   POWER clamp passes 1 mA (typ) near -0.37 V on its own axis
[GND_clamp]
|Voltage   I(typ)   I(min)   I(max)
-2.75V    -14.95A    -8.916A    -17.97A
-1.13V    -1.387A    -1.039A    -846.5mA
-1.04V    -775.3mA   -667.5mA   -226.6mA
-950mV    -294.9mA   -343.6mA   -24.45mA
-860mV    -58.51mA   -114.8mA   -11.13mA
-770mV    -11.55mA   -23.09mA   -8.664mA
-680mV    -5.737mA   -6.117mA   -6.48mA
-590mV    -3.79mA    -3.141mA   -4.402mA
-230mV    -44.51uA   -32.23uA   -16.96uA
5.44V     0A         0A         0A
[POWER_clamp]
|Voltage   I(typ)   I(min)   I(max)
-2.69V    11.16A     7.25A      12.69A
-1.16V    1.281A     1.002A     850.9mA
-1.07V    788.5mA    681.3mA    324.6mA
-980mV    368.1mA    391mA      47.84mA
-890mV    99.61mA    161.5mA    12.91mA
-800mV    18.31mA    39.69mA    9.783mA
-710mV    7.241mA    9.319mA    7.51mA
-620mV    4.876mA    4.494mA    5.346mA
-260mV    201.3uA    213.5uA    41.93uA
5.5V      0A         0A         0A
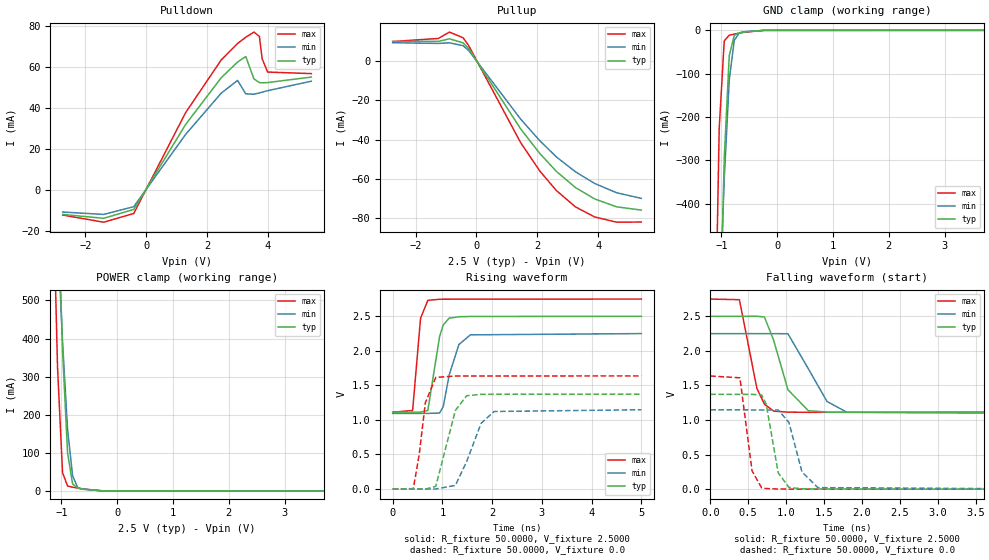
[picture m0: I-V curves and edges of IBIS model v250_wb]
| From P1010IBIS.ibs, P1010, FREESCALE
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[Model] v250_wb
|   Model v250_wb
| This model was characterised for following simulation conditions:
| External (pad) voltage:
|   - Typ: 2.5V,   - Min: 2.25V,   - Max: 2.75V
| Library cells for typ/min/max conditions are connected as defined below:
|  chip_pad - External Pad
|  ipp_do - Core Input
|  ipp_obe - Output Buffer Enable
|  esd_boost - vdd_io
|  gnd_io - gnd_io
|  nbias - nbias
|  nbias_bot - nbias_bot
|  nbias_dc - nbias_dc
|  nbias_top - nbias_top
|  pbias - pbias
|  pbias_bot - pbias_bot
|  pbias_dc - pbias_dc
|  pbias_top - pbias_top
|  v12 - v12
|  v12_dc - v12_dc
|  v12_top - v12_top
|  vdd_d - vdd_d
|  vdd_io - vdd_io
|  vsel[2] - gnd_io
|  vsel[3] - vdd_d
|  vsel[4] - gnd_io
| All other pins connected to ground
Model_type I/O
Polarity   Non-Inverting
Enable   Active-High
Vinl =   0.7500V
Vinh =   1.7500V
Vmeas =  1.2500V
Cref =   0.0F
Rref =   50.0000
Vref =   1.2500V
C_comp   2.1221pF   1.9600pF   2.4667pF
[Temperature Range]   85.0000   0.1250k   -40.0000
[Voltage Range]   2.5000V   2.2500V   2.7500V
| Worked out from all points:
|   slope of the pulldown table from 0 to 0.375 V, typ, clamps not added: 38.9 ohm
|   slope of the pullup table from 0 to 0.375 V, typ, clamps not added: 39.9 ohm
|   GND clamp passes 1 mA (typ) near -0.40 V on its own axis
|   POWER clamp passes 1 mA (typ) near -0.37 V on its own axis
|   rising waveform, R_fixture 50.0000, V_fixture 2.5000: 20-80 % time 180ps typ, 235ps min, 112ps max; typ from 1.11 V to 2.5 V
|   rising waveform, R_fixture 50.0000, V_fixture 0.0: 20-80 % time 275ps typ, 371ps min, 177ps max; typ from 0 V to 1.37 V
|   falling waveform, R_fixture 50.0000, V_fixture 2.5000: 20-80 % time 234ps typ, 336ps min, 160ps max; typ from 2.5 V to 1.11 V
|   falling waveform, R_fixture 50.0000, V_fixture 0.0: 20-80 % time 127ps typ, 169ps min, 96.5ps max; typ from 1.37 V to 0 V
[Pulldown]
|Voltage   I(typ)   I(min)   I(max)
-2.75V    -11.96mA   -10.79mA   -12.27mA
-1.4V     -13.85mA   -11.95mA   -15.75mA
-410mV    -9.504mA   -8.167mA   -11.5mA
1.3V      32.04mA    27.19mA    37.83mA
2.47V     54.84mA    47.31mA    63.54mA
3.01V     62.54mA    53.57mA    71.61mA
3.28V     65.25mA    47.01mA    74.69mA
3.55V     54.3mA     46.83mA    77.2mA
3.73V     52.51mA    47.45mA    75.09mA
3.82V     52.38mA    47.81mA    64.2mA
4V        52.52mA    48.55mA    57.65mA
5.44V     55.2mA     53.18mA    56.9mA
[Pullup]
|Voltage   I(typ)   I(min)   I(max)
-2.75V    9.9mA      9.29mA     9.9mA
-1.25V    9.96mA     8.92mA     11.45mA
-890mV    11.28mA    9.24mA     14.69mA
-440mV    9.214mA    7.771mA    11.81mA
-260mV    6.366mA    5.376mA    7.908mA
1.45V     -34.57mA   -29.59mA   -41.58mA
2.08V     -47.11mA   -40.62mA   -56.03mA
2.62V     -56.14mA   -48.79mA   -65.9mA
3.25V     -64.44mA   -56.41mA   -74.27mA
3.88V     -70.19mA   -62.34mA   -79.38mA
4.6V      -74.22mA   -67.05mA   -82.03mA
5.41V     -75.87mA   -69.91mA   -81.94mA
[GND_clamp]
|Voltage   I(typ)   I(min)   I(max)
-2.75V    -14.95A    -8.916A    -17.97A
-1.13V    -1.387A    -1.039A    -846.5mA
-1.04V    -775.3mA   -667.5mA   -226.6mA
-950mV    -294.9mA   -343.6mA   -24.45mA
-860mV    -58.51mA   -114.8mA   -11.13mA
-770mV    -11.55mA   -23.09mA   -8.664mA
-680mV    -5.737mA   -6.117mA   -6.48mA
-590mV    -3.79mA    -3.141mA   -4.402mA
-230mV    -44.51uA   -32.23uA   -16.96uA
5.44V     0A         0A         0A
[POWER_clamp]
|Voltage   I(typ)   I(min)   I(max)
-2.69V    11.16A     7.25A      12.69A
-1.16V    1.281A     1.002A     850.9mA
-1.07V    788.5mA    681.3mA    324.6mA
-980mV    368.1mA    391mA      47.84mA
-890mV    99.61mA    161.5mA    12.91mA
-800mV    18.31mA    39.69mA    9.783mA
-710mV    7.241mA    9.319mA    7.51mA
-620mV    4.876mA    4.494mA    5.346mA
-260mV    201.3uA    213.5uA    41.93uA
5.5V      0A         0A         0A
[Ramp]
| variable   typ   min   max
dV/dt_r  0.8231/0.2751n   0.6881/0.3712n   0.9819/0.1767n
dV/dt_f  0.8322/0.2342n   0.6935/0.3357n   0.9831/0.1602n
R_load = 50.0000
[Rising Waveform]
R_fixture= 50.0000
V_fixture= 2.5000
V_fixture_min= 2.2500
V_fixture_max= 2.7500
|time   V(typ)   V(min)   V(max)
0s        1.113V     1.094V     1.111V
400.6ps   1.113V     1.094V     1.137V
560.3ps   1.113V     1.094V     2.472V
706.3ps   1.136V     1.094V     2.732V
943.6ps   2.21V      1.1V       2.747V
1.017ns   2.375V     1.193V     2.748V
1.136ns   2.474V     1.651V     2.748V
1.331ns   2.494V     2.091V     2.749V
1.563ns   2.498V     2.232V     2.749V
5ns       2.5V       2.25V      2.75V
[Rising Waveform]
R_fixture= 50.0000
V_fixture= 0.0
V_fixture_min= 0.0
V_fixture_max= 0.0
|time   V(typ)   V(min)   V(max)
0s        11.46uV    23.25uV    1.779uV
414.3ps   -36.43uV   5.787uV    4.619mV
533.5ps   -83.29uV   -7.474uV   499.9mV
655.9ps   -2.986mV   -23.92uV   1.248V
866.1ps   37.64mV    -431.1uV   1.615V
1.261ns   1.138V     51.92mV    1.636V
1.487ns   1.35V      397.7mV    1.636V
1.777ns   1.37V      949.1mV    1.636V
2.038ns   1.371V     1.122V     1.636V
5ns       1.372V     1.147V     1.637V
[Falling Waveform]
R_fixture= 50.0000
V_fixture= 2.5000
V_fixture_min= 2.2500
V_fixture_max= 2.7500
|time   V(typ)   V(min)   V(max)
0s        2.5V       2.25V      2.75V
384.1ps   2.5V       2.25V      2.741V
614.3ps   2.501V     2.25V      1.459V
713.7ps   2.491V     2.25V      1.23V
834.2ps   2.159V     2.25V      1.13V
1.024ns   1.439V     2.248V     1.114V
1.293ns   1.135V     1.742V     1.112V
1.539ns   1.116V     1.269V     1.112V
1.803ns   1.114V     1.112V     1.112V
5ns       1.113V     1.094V     1.111V
[Falling Waveform]
R_fixture= 50.0000
V_fixture= 0.0
V_fixture_min= 0.0
V_fixture_max= 0.0
|time   V(typ)   V(min)   V(max)
0s        1.372V     1.147V     1.637V
390.9ps   1.371V     1.147V     1.611V
550.8ps   1.371V     1.146V     265.7mV
677.1ps   1.363V     1.146V     19.64mV
737.3ps   1.231V     1.146V     9.081mV
895.4ps   237.2mV    1.146V     2.145mV
1.037ns   25.61mV    965.5mV    1.373mV
1.209ns   5.635mV    249.6mV    860uV
1.418ns   1.605mV    22.47mV    496.2uV
5ns       98.66uV    144.2uV    46.47uV
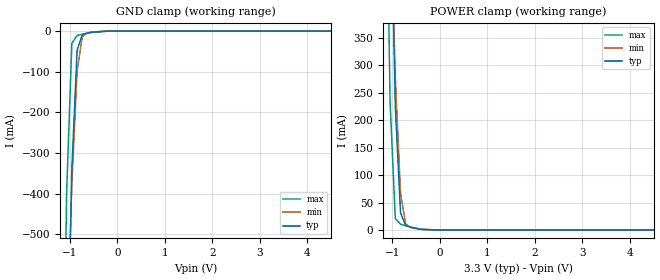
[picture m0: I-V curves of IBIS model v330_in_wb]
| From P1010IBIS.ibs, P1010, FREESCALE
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[Model] v330_in_wb
|   Model v330_in_wb
| This model has derived from v330_wb
| Only applicable curves and parameters are copied
Model_type Input
Polarity   Non-Inverting
Enable   Active-High
Vinl =   0.9900V
Vinh =   2.3100V
C_comp   2.1221pF   1.9600pF   2.4667pF
[Temperature Range]   85.0000   0.1250k   -40.0000
[Voltage Range]   3.3000V   3.0000V   3.6000V
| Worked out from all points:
|   GND clamp passes 1 mA (typ) near -0.40 V on its own axis
|   POWER clamp passes 1 mA (typ) near -0.36 V on its own axis
[GND_clamp]
|Voltage   I(typ)   I(min)   I(max)
-3.6V     -22.25A    -13.16A    -27.15A
-1.18V    -1.756A    -1.257A    -1.286A
-1.07V    -969.3mA   -787.6mA   -396.2mA
-960mV    -338.2mA   -376.1mA   -30.28mA
-850mV    -47.6mA    -98.06mA   -10.8mA
-740mV    -8.434mA   -13.66mA   -7.93mA
-630mV    -4.58mA    -4.071mA   -5.312mA
-520mV    -2.593mA   -2.032mA   -2.91mA
-190mV    -17.06uA   -13.9uA    -5.444uA
7.18V     0A         0A         0A
[POWER_clamp]
|Voltage   I(typ)   I(min)   I(max)
-3.58V    17.06A     10.98A     19.73A
-1.16V    1.281A     1.002A     850.9mA
-1.05V    686.8mA    613.5mA    233.8mA
-940mV    224.1mA    278.8mA    20.58mA
-830mV    31.31mA    66.9mA     10.6mA
-720mV    7.718mA    10.63mA    7.76mA
-610mV    4.705mA    4.29mA     5.119mA
-390mV    1.251mA    1.145mA    864.4uA
-60mV     18.9uA     14.7uA     23.82uA
7.2V      0A         0A         0A
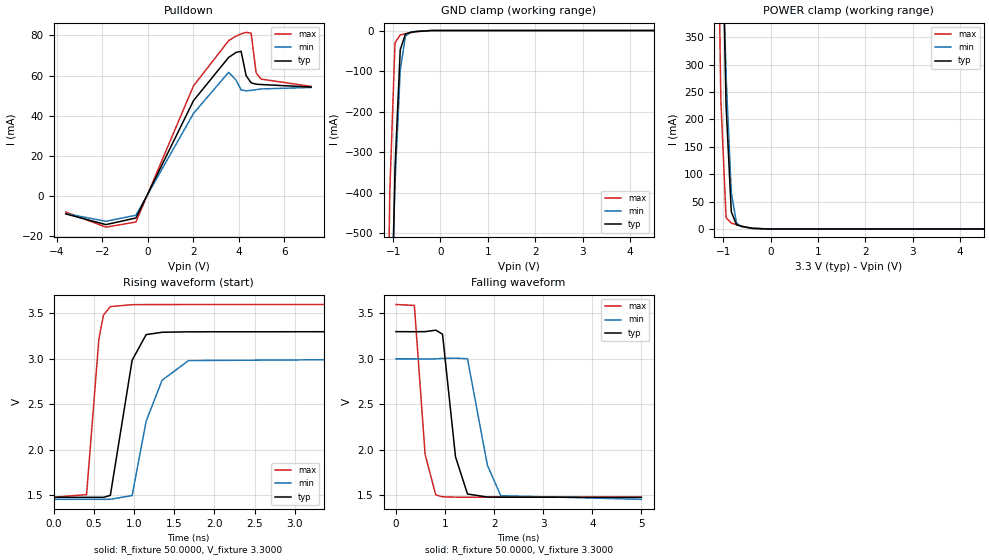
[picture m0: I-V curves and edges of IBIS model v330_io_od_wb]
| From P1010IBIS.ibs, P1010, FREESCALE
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[Model] v330_io_od_wb
|   Model v330_io_od_wb
| This model has derived from v330_wb
| Only applicable curves and parameters are copied
Model_type I/O_open_drain
Polarity   Non-Inverting
Enable   Active-High
Vinl =   0.9900V
Vinh =   2.3100V
Vmeas =  1.6500V
Cref =   0.0F
Rref =   50.0000
Vref =   1.6500V
C_comp   2.1221pF   1.9600pF   2.4667pF
[Temperature Range]   85.0000   0.1250k   -40.0000
[Voltage Range]   3.3000V   3.0000V   3.6000V
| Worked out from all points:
|   slope of the pulldown table from 0 to 0.495 V, typ, clamps not added: 38.4 ohm
|   GND clamp passes 1 mA (typ) near -0.40 V on its own axis
|   POWER clamp passes 1 mA (typ) near -0.36 V on its own axis
|   rising waveform, R_fixture 50.0000, V_fixture 3.3000: 20-80 % time 195ps typ, 264ps min, 107ps max; typ from 1.47 V to 3.3 V
|   falling waveform, R_fixture 50.0000, V_fixture 3.3000: 20-80 % time 211ps typ, 278ps min, 154ps max; typ from 3.3 V to 1.47 V
[Pulldown]
|Voltage   I(typ)   I(min)   I(max)
-3.6V     -8.93mA    -8.74mA    -7.95mA
-1.84V    -14.24mA   -12.6mA    -15.51mA
-520mV    -10.96mA   -9.563mA   -12.95mA
2.01V     47.55mA    41.19mA    54.93mA
3.55V     69.04mA    61.63mA    77.4mA
3.88V     71.59mA    57.74mA    79.69mA
4.1V      72.11mA    52.9mA     80.77mA
4.32V     59.98mA    52.42mA    81.57mA
4.54V     56.41mA    52.64mA    81.16mA
4.76V     55.72mA    52.99mA    61.4mA
4.98V     55.56mA    53.36mA    58.26mA
7.18V     54.3mA     54.1mA     54.6mA
[GND_clamp]
|Voltage   I(typ)   I(min)   I(max)
-3.6V     -22.25A    -13.16A    -27.15A
-1.18V    -1.756A    -1.257A    -1.286A
-1.07V    -969.3mA   -787.6mA   -396.2mA
-960mV    -338.2mA   -376.1mA   -30.28mA
-850mV    -47.6mA    -98.06mA   -10.8mA
-740mV    -8.434mA   -13.66mA   -7.93mA
-630mV    -4.58mA    -4.071mA   -5.312mA
-520mV    -2.593mA   -2.032mA   -2.91mA
-190mV    -17.06uA   -13.9uA    -5.444uA
7.18V     0A         0A         0A
[POWER_clamp]
|Voltage   I(typ)   I(min)   I(max)
-3.58V    17.06A     10.98A     19.73A
-1.16V    1.281A     1.002A     850.9mA
-1.05V    686.8mA    613.5mA    233.8mA
-940mV    224.1mA    278.8mA    20.58mA
-830mV    31.31mA    66.9mA     10.6mA
-720mV    7.718mA    10.63mA    7.76mA
-610mV    4.705mA    4.29mA     5.119mA
-390mV    1.251mA    1.145mA    864.4uA
-60mV     18.9uA     14.7uA     23.82uA
7.2V      0A         0A         0A
[Ramp]
| variable   typ   min   max
dV/dt_r  1.0823/0.2478n   0.9195/0.3115n   1.2729/0.1701n
dV/dt_f  1.0952/0.2110n   0.9285/0.2782n   1.2750/0.1544n
R_load = 50.0000
[Rising Waveform]
R_fixture= 50.0000
V_fixture= 3.3000
V_fixture_min= 3.0000
V_fixture_max= 3.6000
|time   V(typ)   V(min)   V(max)
0s        1.474V     1.452V     1.475V
410.6ps   1.474V     1.452V     1.504V
564.4ps   1.474V     1.452V     3.225V
622ps     1.474V     1.452V     3.483V
706.4ps   1.496V     1.452V     3.576V
977.2ps   2.985V     1.494V     3.597V
1.151ns   3.267V     2.312V     3.598V
1.349ns   3.293V     2.764V     3.598V
1.678ns   3.298V     2.981V     3.599V
5ns       3.3V       2.999V     3.599V
[Falling Waveform]
R_fixture= 50.0000
V_fixture= 3.3000
V_fixture_min= 3.0000
V_fixture_max= 3.6000
|time   V(typ)   V(min)   V(max)
0s        3.3V       3V         3.599V
375.5ps   3.299V     3V         3.589V
594.9ps   3.3V       2.999V     1.945V
811.4ps   3.316V     3V         1.501V
949.4ps   3.272V     3.005V     1.48V
1.214ns   1.92V      3.008V     1.476V
1.458ns   1.511V     3.001V     1.476V
1.864ns   1.477V     1.827V     1.475V
2.136ns   1.476V     1.492V     1.475V
5ns       1.474V     1.452V     1.475V
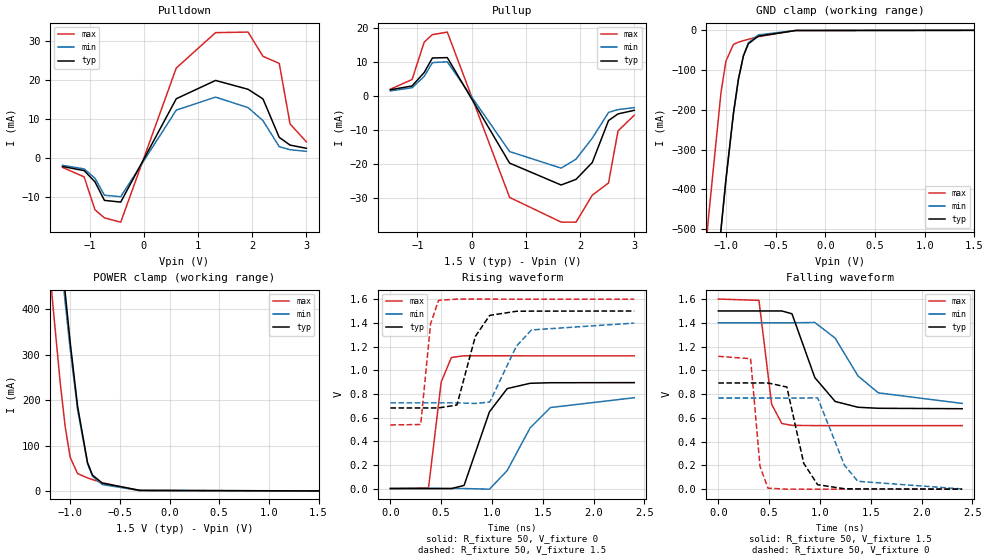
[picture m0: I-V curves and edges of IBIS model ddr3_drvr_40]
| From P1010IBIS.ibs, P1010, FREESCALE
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| * 8520 DDR3 Driver Model - 40 Ohm Setting *
[Model]   ddr3_drvr_40
Model_type I/O
Polarity   Non-Inverting
Vinl = 0.575V
Vinh = 0.925V
Vmeas = 0.75V
Cref = 0
Rref = 50
Vref = 0.75V
|   typ   min   max
C_comp   3.648330e-12   2.038670e-12   4.817820e-12
[Receiver Thresholds]
Vth   =  0.750V
Vinh_ac  =  0.175V
Vinh_dc  =  0.100V
Vinl_ac  = -0.175V
Vinl_dc  = -0.100V
|   typ   min   max
[Voltage range]   1.5V   1.4V   1.6V
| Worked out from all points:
|   slope of the pulldown table from 0 to 0.225 V, typ, clamps not added: 33.1 ohm
|   slope of the pullup table from 0 to 0.225 V, typ, clamps not added: 30.3 ohm
|   GND clamp passes 1 mA (typ) near -0.33 V on its own axis
|   POWER clamp passes 1 mA (typ) near -0.28 V on its own axis
|   falling waveform, R_fixture 50, V_fixture 1.5: 20-80 % time 227ps typ, 336ps min, 84.8ps max; typ from 1.5 V to 0.677 V
|   rising waveform, R_fixture 50, V_fixture 0: 20-80 % time 216ps typ, 319ps min, 86.2ps max; typ from 0 V to 0.895 V
|   falling waveform, R_fixture 50, V_fixture 0: 20-80 % time 138ps typ, 202ps min, 61.1ps max; typ from 0.893 V to 0 V
|   rising waveform, R_fixture 50, V_fixture 1.5: 20-80 % time 152ps typ, 220ps min, 65.2ps max; typ from 0.681 V to 1.5 V
[Pulldown]
| Warnings regarding non-monotonicity are expected
| Voltage   I(typ)   I(min)   I(max)
-1.5V     -2.258mA   -1.956mA   -2.489mA
-1.1V     -3.315mA   -2.878mA   -4.935mA
-900mV    -6.212mA   -5.287mA   -13.42mA
-725mV    -10.99mA   -9.66mA    -15.49mA
-425mV    -11.42mA   -10.04mA   -16.6mA
600mV     15.19mA    12.26mA    23.1mA
1.325V    19.9mA     15.61mA    32.21mA
1.925V    17.62mA    12.9mA     32.35mA
2.2V      15.13mA    9.544mA    26.1mA
2.5V      5.232mA    2.832mA    24.29mA
2.7V      3.246mA    2.057mA    8.688mA
3V        2.432mA    1.653mA    4.1mA
[GND_clamp]
| Voltage   I(typ)   I(min)   I(max)
-1.5V     -1.83A     -1.803A    -1.463A
-1.2V     -918.5mA   -909.4mA   -538.8mA
-1.175V   -846mA     -838.3mA   -467.5mA
-1.05V    -500.5mA   -498.8mA   -155.7mA
-1V       -374.3mA   -374.5mA   -77.03mA
-925mV    -208.7mA   -210.1mA   -35.53mA
-875mV    -123mA     -123.8mA   -29.71mA
-825mV    -64.79mA   -64.04mA   -26.02mA
-775mV    -33.87mA   -31.49mA   -22.62mA
-675mV    -14.65mA   -11.59mA   -16.08mA
-300mV    -558.2uA   -260.8uA   -231.8uA
1.5V      1.426uA    9.416uA    6.886nA
[Pullup]
| Warnings regarding non-monotonicity are expected
| Voltage   I(typ)   I(min)   I(max)
-1.5V     1.812mA    1.473mA    1.978mA
-1.1V     2.927mA    2.406mA    4.821mA
-875mV    6.901mA    5.745mA    15.84mA
-725mV    11.14mA    9.776mA    17.99mA
-450mV    11.25mA    10.02mA    18.74mA
700mV     -19.72mA   -16.33mA   -29.79mA
1.65V     -26.14mA   -21.19mA   -37.03mA
1.925V    -24.49mA   -18.56mA   -37.06mA
2.225V    -19.55mA   -12.4mA    -29.13mA
2.525V    -7.227mA   -4.842mA   -25.54mA
2.7V      -5.272mA   -4.004mA   -10.28mA
3V        -4.225mA   -3.44mA    -5.653mA
[POWER_clamp]
| Warnings about POWER_clamp data never reaching
| zero are expected, and this is okay as long as
| the 0V data are around 10uA or less
| Voltage   I(typ)   I(min)   I(max)
-1.5V     1.587A     1.494A     1.288A
-1.2V     797.2mA    753.3mA    475mA
-1.175V   734.5mA    694.6mA    412.6mA
-1.1V     552mA      523.4mA    238.4mA
-1.05V    436.4mA    415mA      141.5mA
-1V       328.1mA    313.2mA    74.16mA
-925mV    186.2mA    179.4mA    38.2mA
-825mV    62.3mA     59.8mA     28.63mA
-775mV    34.82mA    32mA       25mA
-675mV    17.02mA    14mA       18mA
-300mV    1.425mA    937.9uA    241uA
1.5V      0A         0A         0A
|   typ   min   max
[Ramp]
dV/dt_r   0.536878/2.15232E-10   0.461038/3.20165E-10   0.671656/8.51812E-11
dV/dt_f   0.493706/2.26258E-10   0.407757/3.36731E-10   0.639377/8.30845E-11
[Falling Waveform]
R_fixture = 50
V_fixture = 1.5
V_fixture_min = 1.4
V_fixture_max = 1.6
| Time   V(typ)   V(min)   V(max)
0s        1.5V       1.4V       1.6V
400ps     1.5V       1.4V       1.589V
525ps     1.5V       1.4V       714.2mV
625ps     1.5V       1.4V       552.6mV
725ps     1.476V     1.4V       536.7mV
950ps     938.5mV    1.403V     534.9mV
1.15ns    737.9mV    1.271V     534.8mV
1.375ns   689.1mV    952.3mV    534.8mV
1.575ns   680.5mV    810.5mV    534.7mV
2.4ns     677mV      721.5mV    534.6mV
[Rising Waveform]
R_fixture = 50
V_fixture = 0
V_fixture_min = 0
V_fixture_max = 0
| Time   V(typ)   V(min)   V(max)
0s        59.95uV    33.02uV    160.9nV
375ps     66.66uV    49.78uV    3.789mV
500ps     53.84uV    42.59uV    900mV
600ps     -401.4uV   42.4uV     1.107V
725ps     26.03mV    31.85uV    1.122V
975ps     648.5mV    -5.369mV   1.122V
1.15ns    844.7mV    152.4mV    1.122V
1.375ns   889.3mV    512.6mV    1.121V
1.575ns   894.1mV    684.3mV    1.121V
2.4ns     894.9mV    767.3mV    1.121V
[Falling Waveform]
R_fixture = 50
V_fixture = 0
V_fixture_min = 0
V_fixture_max = 0
| Time   V(typ)   V(min)   V(max)
0s        893.4mV    767mV      1.118V
317.7ps   894mV      767.2mV    1.098V
410.6ps   893.7mV    767.1mV    191mV
488.8ps   893.5mV    767mV      7.903mV
674.5ps   859.6mV    766.9mV    -134.6uV
840.7ps   217.6mV    766.9mV    -317.4uV
977.5ps   37.04mV    768.1mV    -317.5uV
1.241ns   3.371mV    202mV      -317.4uV
1.373ns   1.743mV    65.83mV    -317.4uV
2.4ns     203.4uV    1.342mV    -317.4uV
[Rising Waveform]
R_fixture = 50
V_fixture = 1.5
V_fixture_min = 1.4
V_fixture_max = 1.6
| Time   V(typ)   V(min)   V(max)
0s        680.9mV    723.8mV    537.3mV
298.1ps   680.9mV    723.9mV    541mV
395.9ps   680.9mV    723.8mV    1.394V
474.1ps   680.9mV    723.7mV    1.59V
654.9ps   706mV      723.7mV    1.601V
835.8ps   1.285V     718.5mV    1.601V
977.5ps   1.463V     730.7mV    1.601V
1.241ns   1.498V     1.204V     1.6V
1.388ns   1.499V     1.34V      1.6V
2.4ns     1.5V       1.398V     1.6V
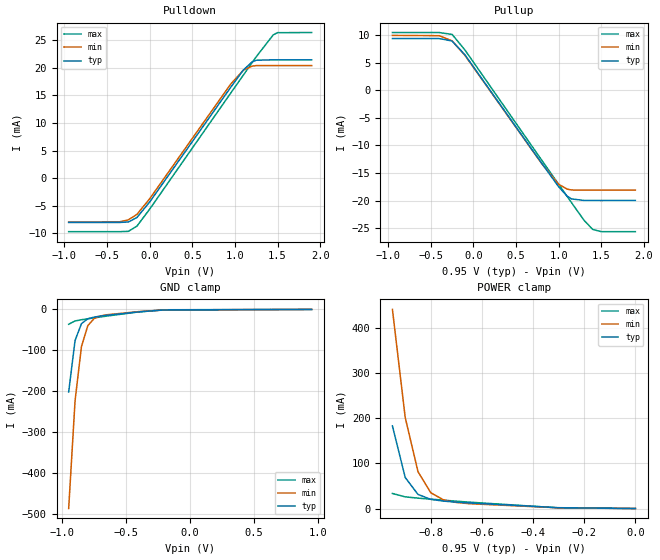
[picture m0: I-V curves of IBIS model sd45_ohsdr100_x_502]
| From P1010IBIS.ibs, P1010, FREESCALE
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[Model] sd45_ohsdr100_x_502
Model_type 3-state
Enable Active-High
Polarity Non-Inverting
|   TYP   MIN   MAX
C_comp   1.60pF   1.60pF   1.67pF
[Model Spec]
Vmeas   0.475   0.425   0.605
[Voltage Range]   0.95   0.85   1.21
[Temperature Range] 65   125   -40
[Driver Schedule]
sd45_ohsdr100_x_50   0ps   NA   0ps   NA
sd45_ohsdr100_x_52  333.33ps   NA  333.33ps   NA
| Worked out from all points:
|   slope of the pulldown table from 0 to 0.142 V, typ, clamps not added: 45.7 ohm
|   slope of the pullup table from 0 to 0.142 V, typ, clamps not added: 45.5 ohm
|   GND clamp passes 1 mA (typ) near -0.19 V on its own axis
|   POWER clamp passes 1 mA (typ) near -0.25 V on its own axis
[Pullup]
|   Vout(V)   TYP   WCS   BCS
-950mV    9.394mA    9.972mA    10.49mA
-400mV    9.394mA    9.921mA    10.49mA
-250mV    8.951mA    8.974mA    10.15mA
-100mV    6.461mA    6.356mA    7.34mA
800mV     -13.2mA    -13.28mA   -12.64mA
1V        -17.5mA    -17.05mA   -17.05mA
1.1V      -19.21mA   -17.92mA   -19.26mA
1.15V     -19.7mA    -18.08mA   -20.36mA
1.3V      -19.98mA   -18.11mA   -23.62mA
1.4V      -19.98mA   -18.11mA   -25.24mA
1.5V      -19.98mA   -18.11mA   -25.64mA
1.9V      -19.98mA   -18.11mA   -25.64mA
[Pulldown]
|   Vout(V)   TYP   WCS   BCS
-950mV    -8.027mA   -7.945mA   -9.693mA
-350mV    -8.027mA   -7.908mA   -9.693mA
-250mV    -7.938mA   -7.555mA   -9.642mA
-150mV    -7.144mA   -6.573mA   -8.705mA
0V        -4.323mA   -3.744mA   -5.622mA
950mV     16.44mA    17.03mA    15.39mA
1.1V      19.6mA     19.57mA    18.69mA
1.2V      21.04mA    20.28mA    20.89mA
1.25V     21.36mA    20.39mA    21.99mA
1.45V     21.44mA    20.39mA    25.96mA
1.5V      21.44mA    20.39mA    26.36mA
1.9V      21.44mA    20.39mA    26.38mA
[GND Clamp]
|   Vout(V)   TYP   WCS   BCS
-950mV    -201.6mA   -486.5mA   -36.16mA
-900mV    -75.75mA   -222.9mA   -28.05mA
-850mV    -34.66mA   -90.59mA   -25.11mA
-800mV    -22.71mA   -39.37mA   -22.78mA
-750mV    -18.57mA   -21.91mA   -20.52mA
-700mV    -16.25mA   -15.71mA   -18.29mA
-650mV    -14.32mA   -12.88mA   -16.07mA
-400mV    -5.858mA   -5.175mA   -5.911mA
-200mV    -1.108mA   -1.072mA   -756.7uA
950mV     70.01uA    122.9uA    16.34uA
[POWER Clamp]
|   Vout(V)   TYP   WCS   BCS
-950mV    183.5mA    442.2mA    33.42mA
-900mV    68.86mA    202.2mA    25.88mA
-850mV    31.34mA    81.75mA    23.04mA
-800mV    20.35mA    35.06mA    20.76mA
-750mV    16.45mA    19.08mA    18.55mA
-700mV    14.21mA    13.35mA    16.36mA
-650mV    12.35mA    10.71mA    14.18mA
-300mV    1.805mA    1.559mA    1.409mA
0V        0A         0A         0A
[Ramp]
R_load=50.00
dV/dt_r  1.7449e-01/6.4215e-11  1.5361e-01/6.5528e-11  2.2871e-01/6.5586e-11
dV/dt_f  1.7449e-01/6.5823e-11  1.5361e-01/6.7896e-11  2.2872e-01/6.6497e-11
| End [Model] sd45_ohsdr100_x_502
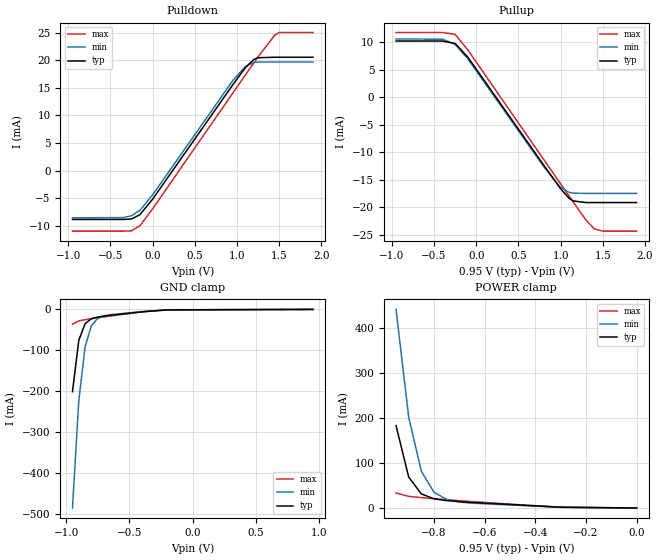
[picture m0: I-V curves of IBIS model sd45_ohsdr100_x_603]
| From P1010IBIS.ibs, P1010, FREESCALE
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[Model] sd45_ohsdr100_x_603
Model_type 3-state
Enable Active-High
Polarity Non-Inverting
|   TYP   MIN   MAX
C_comp   1.60pF   1.60pF   1.67pF
[Model Spec]
Vmeas   0.475   0.425   0.605
[Voltage Range]   0.95   0.85   1.21
[Temperature Range] 65   125   -40
[Driver Schedule]
sd45_ohsdr100_x_60   0ps   NA   0ps   NA
sd45_ohsdr100_x_63  333.33ps   NA  333.33ps   NA
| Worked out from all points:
|   slope of the pulldown table from 0 to 0.142 V, typ, clamps not added: 45.7 ohm
|   slope of the pullup table from 0 to 0.142 V, typ, clamps not added: 45.5 ohm
|   GND clamp passes 1 mA (typ) near -0.19 V on its own axis
|   POWER clamp passes 1 mA (typ) near -0.25 V on its own axis
[Pullup]
|   Vout(V)   TYP   WCS   BCS
-950mV    10.25mA    10.63mA    11.8mA
-400mV    10.25mA    10.58mA    11.8mA
-250mV    9.815mA    9.637mA    11.46mA
-100mV    7.328mA    7.022mA    8.649mA
800mV     -12.33mA   -12.61mA   -11.31mA
1V        -16.63mA   -16.39mA   -15.73mA
1.1V      -18.35mA   -17.27mA   -17.94mA
1.15V     -18.84mA   -17.43mA   -19.04mA
1.3V      -19.13mA   -17.47mA   -22.31mA
1.4V      -19.13mA   -17.47mA   -23.93mA
1.5V      -19.13mA   -17.47mA   -24.33mA
1.9V      -19.13mA   -17.47mA   -24.33mA
[Pulldown]
|   Vout(V)   TYP   WCS   BCS
-950mV    -8.881mA   -8.579mA   -11mA
-350mV    -8.881mA   -8.549mA   -11mA
-250mV    -8.795mA   -8.206mA   -10.95mA
-150mV    -8.006mA   -7.229mA   -10.02mA
0V        -5.189mA   -4.405mA   -6.939mA
950mV     15.58mA    16.36mA    14.07mA
1.1V      18.73mA    18.9mA     17.38mA
1.2V      20.18mA    19.62mA    19.58mA
1.25V     20.49mA    19.73mA    20.68mA
1.45V     20.58mA    19.73mA    24.65mA
1.5V      20.58mA    19.73mA    25.06mA
1.9V      20.58mA    19.73mA    25.07mA
[GND Clamp]
|   Vout(V)   TYP   WCS   BCS
-950mV    -201.6mA   -486.5mA   -36.16mA
-900mV    -75.75mA   -222.9mA   -28.05mA
-850mV    -34.66mA   -90.59mA   -25.11mA
-800mV    -22.71mA   -39.37mA   -22.78mA
-750mV    -18.57mA   -21.91mA   -20.52mA
-700mV    -16.25mA   -15.71mA   -18.29mA
-650mV    -14.32mA   -12.88mA   -16.07mA
-400mV    -5.858mA   -5.175mA   -5.911mA
-200mV    -1.108mA   -1.072mA   -756.7uA
950mV     70.01uA    122.9uA    16.34uA
[POWER Clamp]
|   Vout(V)   TYP   WCS   BCS
-950mV    183.5mA    442.2mA    33.41mA
-900mV    68.86mA    202.2mA    25.88mA
-850mV    31.34mA    81.75mA    23.04mA
-800mV    20.35mA    35.06mA    20.76mA
-750mV    16.45mA    19.08mA    18.55mA
-700mV    14.21mA    13.35mA    16.36mA
-650mV    12.35mA    10.71mA    14.18mA
-300mV    1.805mA    1.559mA    1.409mA
0V        0A         0A         0A
[Ramp]
R_load=50.00
dV/dt_r  1.4958e-01/6.4236e-11  1.3455e-01/6.5371e-11  1.9119e-01/6.5914e-11
dV/dt_f  1.4958e-01/6.5678e-11  1.3454e-01/6.7506e-11  1.9120e-01/6.6813e-11
| End [Model] sd45_ohsdr100_x_603
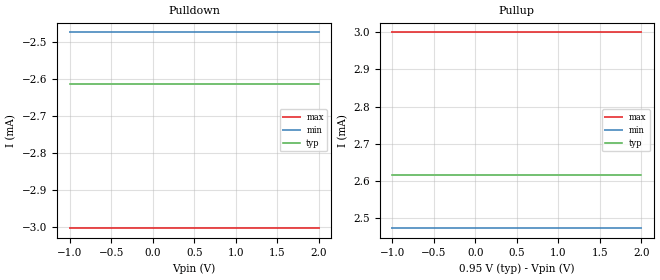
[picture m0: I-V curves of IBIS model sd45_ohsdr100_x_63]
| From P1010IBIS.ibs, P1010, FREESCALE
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[Model] sd45_ohsdr100_x_63
Model_type 3-state
Enable Active-High
Polarity Non-Inverting
|   TYP   MIN   MAX
C_comp   0.00pF   0.00pF   0.00pF
[Model Spec]
Vmeas   0.475   0.425   0.605
[Temperature Range] 65   125   -40
[Voltage Range]   0.95   0.85   1.21
[Pullup]
|   Vout(V)   TYP   WCS   BCS
-1V       2.615mA    2.472mA    3mA
2V        2.615mA    2.472mA    3mA
[Pulldown]
|   Vout(V)   TYP   WCS   BCS
-1V       -2.614mA   -2.474mA   -3.003mA
2V        -2.614mA   -2.474mA   -3.003mA
[GND Clamp]
|   Vout(V)   TYP   WCS   BCS
-1V       0A         0A         0A
1V        0A         0A         0A
[POWER Clamp]
|   Vout(V)   TYP   WCS   BCS
-1V       0A         0A         0A
0V        0A         0A         0A
[Ramp]
R_load=50
dV/dt_r  1.4958e-01/6.4236e-11  1.3455e-01/6.5371e-11  1.9119e-01/6.5914e-11
dV/dt_f  1.4958e-01/6.5678e-11  1.3454e-01/6.7506e-11  1.9120e-01/6.6813e-11
| End [Model] sd45_ohsdr100_x_63
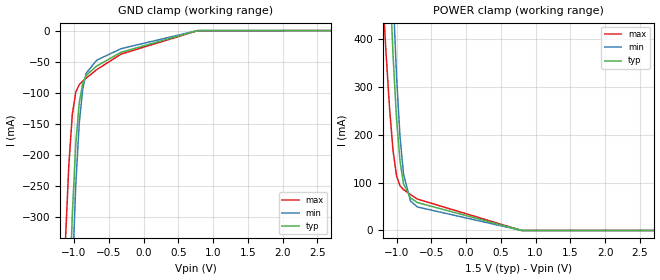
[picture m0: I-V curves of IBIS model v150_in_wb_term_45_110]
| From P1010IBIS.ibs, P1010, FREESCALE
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[Model]  v150_in_wb_term_45_110
|   Model v150_in_wb_term_45_110
| This model has derived from v150_wb_term_45_110
| Only applicable curves and parameters are copied
Model_type Input
Polarity   Non-Inverting
Enable   Active-High
Vinl =   0.5750V
Vinh =   0.9250V
C_comp   1.8300pF   1.6072pF   2.1267pF
[Receiver Thresholds]
Vth   =  0.750V
Vinh_ac  =  0.175V
Vinh_dc  =  0.100V
Vinl_ac  = -0.175V
Vinl_dc  = -0.100V
[Temperature Range]   65.0000   0.1050k   -40.0000
[Voltage Range]   1.5000V   1.4250V   1.5750V
[GND_clamp]
|Voltage   I(typ)   I(min)   I(max)
-1.575V   -3.191A    -3.74A     -2.112A
-1.125V   -657.7mA   -832.5mA   -341.9mA
-1.075V   -458mA     -595.4mA   -216.6mA
-1.025V   -296.8mA   -397.9mA   -135.1mA
-975mV    -182.6mA   -248mA     -99.16mA
-925mV    -116.1mA   -148.9mA   -87.21mA
-875mV    -85.19mA   -94.23mA   -81.47mA
-825mV    -72.19mA   -68.76mA   -76.71mA
-675mV    -57.21mA   -47.79mA   -63.09mA
-325mV    -35.06mA   -29.22mA   -38.02mA
775mV     0A         0A         -222.6uA
3.15V     0A         0A         0A
[POWER_clamp]
|Voltage   I(typ)   I(min)   I(max)
-1.575V   2.923A     3.691A     1.657A
-1.2V     952.5mA    1.24A      496.7mA
-1.15V    732.6mA    963.6mA    367.5mA
-1.1V     534.2mA    713.1mA    254.2mA
-1.05V    364.7mA    496.2mA    166.3mA
-1V       232.7mA    321.4mA    114.1mA
-950mV    144.7mA    195.4mA    93.22mA
-900mV    97.72mA    118.3mA    85.31mA
-800mV    67.95mA    61.71mA    75.17mA
-700mV    58.33mA    49.11mA    65.64mA
800mV     0A         0A         0A
3.15V     0A         0A         0A
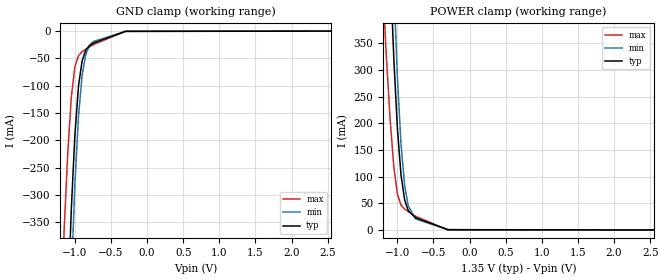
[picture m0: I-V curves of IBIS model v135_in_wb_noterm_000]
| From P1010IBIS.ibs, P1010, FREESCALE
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[Model]  v135_in_wb_noterm_000
|   Model v135_in_wb_noterm_000
| This model has derived from v135_wb_noterm_000
| Only applicable curves and parameters are copied
Model_type Input
Polarity   Non-Inverting
Enable   Active-High
Vinl =   0.5150V
Vinh =   0.9350V
C_comp   2.1708pF   1.9051pF   2.5197pF
[Receiver Thresholds]
Vth   =  0.675V
Vinh_ac  =  0.160V
Vinh_dc  =  0.090V
Vinl_ac  = -0.160V
Vinl_dc  = -0.090V
[Temperature Range]   65.0000   0.1050k   -40.0000
[Voltage Range]   1.3500V   1.2830V   1.4500V
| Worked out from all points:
|   GND clamp passes 1 mA (typ) near -0.33 V on its own axis
|   POWER clamp passes 1 mA (typ) near -0.33 V on its own axis
[GND_clamp]
|Voltage   I(typ)   I(min)   I(max)
-1.45V    -2.38A     -2.835A    -1.524A
-1.15V    -725.1mA   -926.7mA   -367.7mA
-1.1V     -509.6mA   -673mA     -226.1mA
-1.05V    -328.1mA   -454.6mA   -121.7mA
-1V       -189.9mA   -280.1mA   -65.05mA
-950mV    -100.6mA   -155.8mA   -44.8mA
-900mV    -54.56mA   -80.76mA   -37.75mA
-850mV    -35.07mA   -43.18mA   -33.28mA
-800mV    -26.84mA   -26.77mA   -29.19mA
-750mV    -22.25mA   -19.45mA   -25.19mA
-300mV    -565.5uA   -393.8uA   -354.4uA
2.9V      0A         0A         0A
[POWER_clamp]
|Voltage   I(typ)   I(min)   I(max)
-1.45V    2.189A     2.803A     1.202A
-1.2V     910.6mA    1.206A     448.3mA
-1.15V    690.6mA    929.2mA    319.2mA
-1.1V     492.2mA    678.6mA    206.3mA
-1.05V    322.7mA    461.7mA    118.9mA
-1V       190.9mA    286.9mA    67.11mA
-950mV    103.2mA    161.1mA    46.73mA
-900mV    56.62mA    84.14mA    39.28mA
-850mV    36.43mA    45.3mA     34.49mA
-750mV    22.99mA    20.76mA    25.77mA
-300mV    503.7uA    581.4uA    77.05uA
2.9V      0A         0A         0A
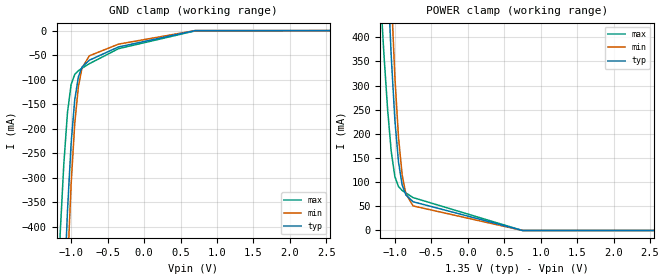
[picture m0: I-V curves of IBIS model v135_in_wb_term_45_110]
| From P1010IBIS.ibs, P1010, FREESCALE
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[Model]  v135_in_wb_term_45_110
|   Model v135_in_wb_term_45_110
| This model has derived from v135_wb_term_45_110
| Only applicable curves and parameters are copied
Model_type Input
Polarity   Non-Inverting
Enable   Active-High
Vinl =   0.5150V
Vinh =   0.9350V
C_comp   1.8374pF   1.6145pF   2.1310pF
[Receiver Thresholds]
Vth   =  0.675V
Vinh_ac  =  0.160V
Vinh_dc  =  0.090V
Vinl_ac  = -0.160V
Vinl_dc  = -0.090V
[Temperature Range]   65.0000   0.1050k   -40.0000
[Voltage Range]   1.3500V   1.2830V   1.4500V
[GND_clamp]
|Voltage   I(typ)   I(min)   I(max)
-1.45V    -2.42A     -2.867A    -1.571A
-1.15V    -765.8mA   -960.1mA   -414.2mA
-1.1V     -550.4mA   -706.5mA   -272.3mA
-1.05V    -368.8mA   -488.1mA   -167.3mA
-1V       -230.4mA   -313.6mA   -110.1mA
-950mV    -140.8mA   -189.2mA   -89.35mA
-900mV    -94.32mA   -113.9mA   -81.76mA
-850mV    -74.33mA   -76.05mA   -76.74mA
-750mV    -60.4mA    -51.48mA   -67.53mA
-350mV    -33.39mA   -27.66mA   -36.91mA
700mV     0A         0A         -672.4uA
2.9V      0A         0A         0A
[POWER_clamp]
|Voltage   I(typ)   I(min)   I(max)
-1.45V    2.226A     2.833A     1.248A
-1.2V     949mA      1.237A     494.3mA
-1.15V    729.1mA    960.4mA    365mA
-1.1V     530.8mA    710mA      251.8mA
-1.05V    361.3mA    493.1mA    163.9mA
-1V       229.3mA    318.3mA    111.7mA
-950mV    141.4mA    192.4mA    90.82mA
-900mV    94.45mA    115.2mA    82.91mA
-850mV    73.83mA    76.12mA    77.67mA
-750mV    59.46mA    50.84mA    68.02mA
750mV     0A         0A         0A
2.9V      0A         0A         0A
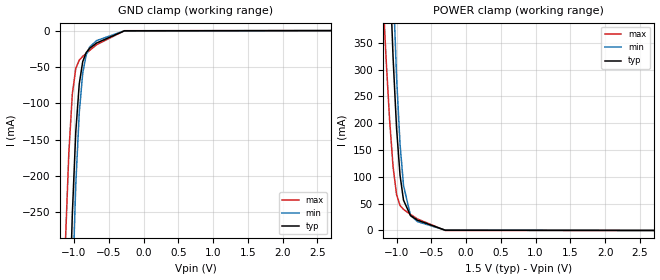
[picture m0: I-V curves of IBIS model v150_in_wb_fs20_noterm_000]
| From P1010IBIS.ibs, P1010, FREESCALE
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[Model]  v150_in_wb_fs20_noterm_000
|   Model v150_in_wb_fs20_noterm_000
| This model has derived from v150_wb_fs20_noterm_000
| Only applicable curves and parameters are copied
Model_type Input
Polarity   Non-Inverting
Enable   Active-High
Vinl =   0.5750V
Vinh =   0.9250V
C_comp   2.1645pF   1.8991pF   2.5155pF
[Receiver Thresholds]
Vth   =  0.750V
Vinh_ac  =  0.175V
Vinh_dc  =  0.100V
Vinl_ac  = -0.175V
Vinl_dc  = -0.100V
[Temperature Range]   65.0000   0.1050k   -40.0000
[Voltage Range]   1.5000V   1.4250V   1.5750V
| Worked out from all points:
|   GND clamp passes 1 mA (typ) near -0.33 V on its own axis
|   POWER clamp passes 1 mA (typ) near -0.33 V on its own axis
[GND_clamp]
|Voltage   I(typ)   I(min)   I(max)
-1.575V   -3.148A    -3.704A    -2.063A
-1.125V   -613.7mA   -795.9mA   -293.2mA
-1.075V   -414mA     -558.8mA   -168.3mA
-1.025V   -253.1mA   -361.4mA   -87.41mA
-975mV    -139.1mA   -211.5mA   -52.01mA
-925mV    -73.08mA   -112.7mA   -40.6mA
-875mV    -42.63mA   -58.32mA   -35.42mA
-825mV    -30.19mA   -33.25mA   -31.22mA
-775mV    -24.33mA   -22.46mA   -27.18mA
-675mV    -17.02mA   -13.78mA   -19.37mA
-275mV    -342.7uA   -243uA     -187.5uA
3.15V     0A         0A         0A
[POWER_clamp]
|Voltage   I(typ)   I(min)   I(max)
-1.575V   2.883A     3.658A     1.608A
-1.2V     910.6mA    1.206A     448.3mA
-1.15V    690.6mA    929.2mA    319.2mA
-1.1V     492.2mA    678.6mA    206.3mA
-1.05V    322.7mA    461.7mA    118.9mA
-1V       190.9mA    286.9mA    67.11mA
-950mV    103.2mA    161.1mA    46.73mA
-900mV    56.63mA    84.15mA    39.28mA
-800mV    27.81mA    28.3mA     30.08mA
-700mV    19.22mA    16.58mA    21.56mA
-300mV    504.3uA    581.9uA    77.17uA
3.15V     0A         0A         0A
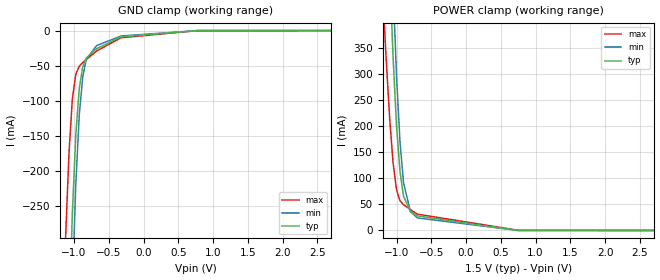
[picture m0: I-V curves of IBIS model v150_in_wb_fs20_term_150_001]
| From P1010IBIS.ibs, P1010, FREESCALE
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[Model]  v150_in_wb_fs20_term_150_001
|   Model v150_in_wb_fs20_term_150_001
| This model has derived from v150_wb_fs20_term_150_001
| Only applicable curves and parameters are copied
Model_type Input
Polarity   Non-Inverting
Enable   Active-High
Vinl =   0.5750V
Vinh =   0.9250V
C_comp   2.0335pF   1.7864pF   2.3564pF
[Receiver Thresholds]
Vth   =  0.750V
Vinh_ac  =  0.175V
Vinh_dc  =  0.100V
Vinl_ac  = -0.175V
Vinl_dc  = -0.100V
[Temperature Range]   65.0000   0.1050k   -40.0000
[Voltage Range]   1.5000V   1.4250V   1.5750V
[GND_clamp]
|Voltage   I(typ)   I(min)   I(max)
-1.575V   -3.157A    -3.712A    -2.072A
-1.125V   -622.5mA   -803.3mA   -303.9mA
-1.075V   -423mA     -566.3mA   -179mA
-1.025V   -262.2mA   -368.9mA   -97.94mA
-975mV    -148.4mA   -219.2mA   -62.42mA
-925mV    -82.34mA   -120.5mA   -50.89mA
-875mV    -51.84mA   -66.16mA   -45.58mA
-825mV    -39.3mA    -41.07mA   -41.26mA
-675mV    -25.78mA   -21.35mA   -29.09mA
-325mV    -9.107mA   -7.667mA   -10.25mA
775mV     0A         0A         -83.66uA
3.15V     0A         0A         0A
[POWER_clamp]
|Voltage   I(typ)   I(min)   I(max)
-1.575V   2.891A     3.665A     1.618A
-1.2V     919.1mA    1.213A     458.6mA
-1.15V    699.2mA    936.4mA    329.7mA
-1.1V     500.9mA    685.9mA    216.8mA
-1.05V    331.6mA    469mA      129.3mA
-1V       199.9mA    294.4mA    77.41mA
-950mV    112.3mA    168.7mA    56.91mA
-900mV    65.63mA    91.77mA    49.34mA
-800mV    36.63mA    35.86mA    39.92mA
-700mV    27.84mA    23.97mA    31.22mA
750mV     0A         0A         362.4uA
3.15V     0A         0A         0A
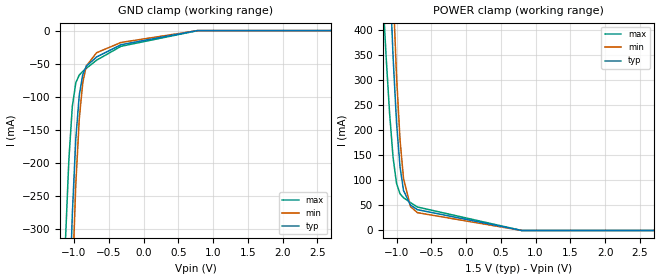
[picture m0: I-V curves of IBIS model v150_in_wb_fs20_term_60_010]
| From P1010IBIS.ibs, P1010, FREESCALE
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[Model]  v150_in_wb_fs20_term_60_010
|   Model v150_in_wb_fs20_term_60_010
| This model has derived from v150_wb_fs20_term_60_010
| Only applicable curves and parameters are copied
Model_type Input
Polarity   Non-Inverting
Enable   Active-High
Vinl =   0.5750V
Vinh =   0.9250V
C_comp   1.9141pF   1.6808pF   2.2180pF
[Receiver Thresholds]
Vth   =  0.750V
Vinh_ac  =  0.175V
Vinh_dc  =  0.100V
Vinl_ac  = -0.175V
Vinl_dc  = -0.100V
[Temperature Range]   65.0000   0.1050k   -40.0000
[Voltage Range]   1.5000V   1.4250V   1.5750V
[GND_clamp]
|Voltage   I(typ)   I(min)   I(max)
-1.575V   -3.171A    -3.724A    -2.089A
-1.125V   -637.9mA   -816.2mA   -320.9mA
-1.075V   -438.4mA   -579.2mA   -195.8mA
-1.025V   -277.5mA   -381.9mA   -114.5mA
-975mV    -163.5mA   -232.1mA   -78.83mA
-925mV    -97.28mA   -133.3mA   -67.11mA
-875mV    -66.58mA   -78.81mA   -61.63mA
-825mV    -53.85mA   -53.56mA   -57.14mA
-675mV    -39.78mA   -33.38mA   -44.64mA
-325mV    -21.28mA   -17.96mA   -23.75mA
775mV     0A         0A         -156.7uA
3.15V     0A         0A         0A
[POWER_clamp]
|Voltage   I(typ)   I(min)   I(max)
-1.575V   2.905A     3.676A     1.634A
-1.2V     933.8mA    1.225A     475.6mA
-1.15V    714mA      948.7mA    346.5mA
-1.1V     515.8mA    698.3mA    233.5mA
-1.05V    346.4mA    481.5mA    145.7mA
-1V       214.6mA    306.8mA    93.72mA
-950mV    126.8mA    181mA      73.06mA
-900mV    80mA       103.9mA    65.33mA
-800mV    50.66mA    47.74mA    55.65mA
-700mV    41.54mA    35.56mA    46.82mA
800mV     0A         0A         0A
3.15V     0A         0A         0A
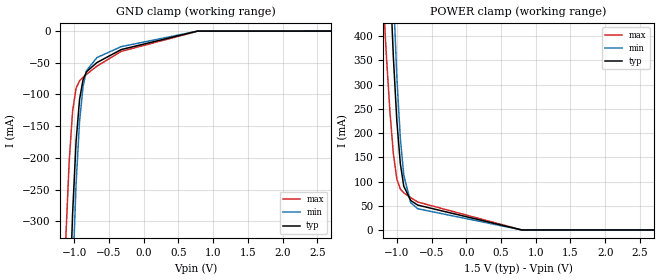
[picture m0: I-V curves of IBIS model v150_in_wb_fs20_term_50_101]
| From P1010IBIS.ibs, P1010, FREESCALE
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[Model]  v150_in_wb_fs20_term_50_101
|   Model v150_in_wb_fs20_term_50_101
| This model has derived from v150_wb_fs20_term_50_101
| Only applicable curves and parameters are copied
Model_type Input
Polarity   Non-Inverting
Enable   Active-High
Vinl =   0.5750V
Vinh =   0.9250V
C_comp   1.8384pF   1.6141pF   2.1387pF
[Receiver Thresholds]
Vth   =  0.750V
Vinh_ac  =  0.175V
Vinh_dc  =  0.100V
Vinl_ac  = -0.175V
Vinl_dc  = -0.100V
[Temperature Range]   65.0000   0.1050k   -40.0000
[Voltage Range]   1.5000V   1.4250V   1.5750V
[GND_clamp]
|Voltage   I(typ)   I(min)   I(max)
-1.575V   -3.183A    -3.733A    -2.102A
-1.125V   -649.2mA   -825.8mA   -332.8mA
-1.075V   -449.5mA   -588.8mA   -207.6mA
-1.025V   -288.5mA   -391.3mA   -126.2mA
-975mV    -174.3mA   -241.4mA   -90.34mA
-925mV    -108mA     -142.4mA   -78.5mA
-875mV    -77.1mA    -87.81mA   -72.89mA
-825mV    -64.21mA   -62.42mA   -68.29mA
-675mV    -49.68mA   -41.82mA   -55.32mA
-325mV    -29.14mA   -24.56mA   -32.02mA
775mV     0A         0A         -231.7uA
3.15V     0A         0A         0A
[POWER_clamp]
|Voltage   I(typ)   I(min)   I(max)
-1.575V   2.916A     3.686A     1.647A
-1.2V     945mA      1.235A     487.7mA
-1.15V    725.1mA    958.1mA    358.5mA
-1.1V     526.8mA    707.6mA    245.3mA
-1.05V    357.2mA    490.7mA    157.4mA
-1V       225.3mA    315.9mA    105.3mA
-950mV    137.4mA    189.9mA    84.48mA
-900mV    90.41mA    112.8mA    76.66mA
-800mV    60.79mA    56.32mA    66.84mA
-700mV    51.4mA     43.87mA    57.74mA
800mV     0A         0A         0A
3.15V     0A         0A         0A
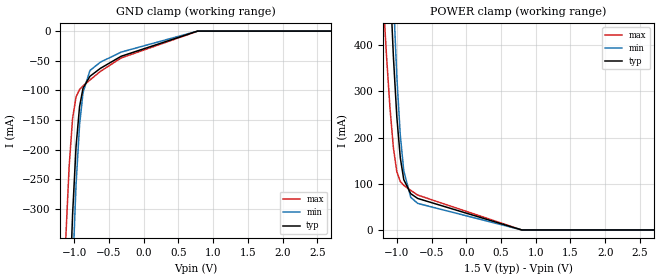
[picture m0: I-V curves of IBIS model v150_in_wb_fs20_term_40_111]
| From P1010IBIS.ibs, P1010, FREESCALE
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[Model]  v150_in_wb_fs20_term_40_111
|   Model v150_in_wb_fs20_term_40_111
| This model has derived from v150_wb_fs20_term_40_111
| Only applicable curves and parameters are copied
Model_type Input
Polarity   Non-Inverting
Enable   Active-High
Vinl =   0.5750V
Vinh =   0.9250V
C_comp   1.7790pF   1.5609pF   2.0778pF
[Receiver Thresholds]
Vth   =  0.750V
Vinh_ac  =  0.175V
Vinh_dc  =  0.100V
Vinl_ac  = -0.175V
Vinl_dc  = -0.100V
[Temperature Range]   65.0000   0.1050k   -40.0000
[Voltage Range]   1.5000V   1.4250V   1.5750V
[GND_clamp]
|Voltage   I(typ)   I(min)   I(max)
-1.575V   -3.205A    -3.752A    -2.126A
-1.125V   -670mA     -843.1mA   -354.3mA
-1.075V   -470.1mA   -605.8mA   -228.7mA
-1.025V   -308.7mA   -408.1mA   -147mA
-975mV    -194.2mA   -257.9mA   -110.8mA
-925mV    -127.5mA   -158.6mA   -98.5mA
-875mV    -96.24mA   -103.7mA   -92.45mA
-775mV    -76.19mA   -66.4mA    -82.41mA
-625mV    -62.85mA   -52.43mA   -67.99mA
-325mV    -42.41mA   -35.4mA    -45.27mA
775mV     0A         0A         -250.4uA
3.15V     0A         0A         0A
[POWER_clamp]
|Voltage   I(typ)   I(min)   I(max)
-1.575V   2.937A     3.702A     1.671A
-1.2V     965.1mA    1.251A     509.7mA
-1.15V    745mA      974.2mA    380.2mA
-1.1V     546.4mA    723.5mA    266.7mA
-1.05V    376.6mA    506.4mA    178.5mA
-1V       244.3mA    331.3mA    126mA
-950mV    156.2mA    205.1mA    104.8mA
-900mV    108.9mA    127.7mA    96.61mA
-800mV    78.54mA    70.71mA    85.79mA
-700mV    68.28mA    57.56mA    75.57mA
800mV     0A         0A         0A
3.15V     0A         0A         0A
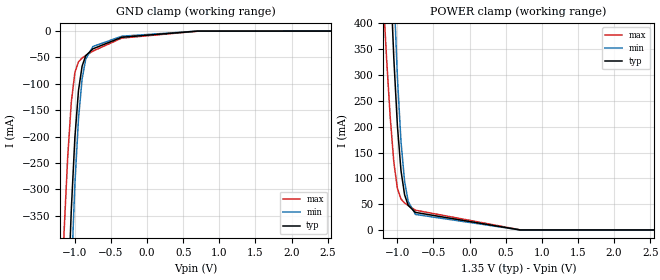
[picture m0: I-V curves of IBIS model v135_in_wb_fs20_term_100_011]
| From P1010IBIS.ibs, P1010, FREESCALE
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[Model]  v135_in_wb_fs20_term_100_011
|   Model v135_in_wb_fs20_term_100_011
| This model has derived from v135_wb_fs20_term_100_011
| Only applicable curves and parameters are copied
Model_type Input
Polarity   Non-Inverting
Enable   Active-High
Vinl =   0.5150V
Vinh =   0.9350V
C_comp   2.0241pF   1.7770pF   2.3401pF
[Receiver Thresholds]
Vth   =  0.675V
Vinh_ac  =  0.160V
Vinh_dc  =  0.090V
Vinl_ac  = -0.160V
Vinl_dc  = -0.090V
[Temperature Range]   65.0000   0.1050k   -40.0000
[Voltage Range]   1.3500V   1.2830V   1.4500V
[GND_clamp]
|Voltage   I(typ)   I(min)   I(max)
-1.45V    -2.391A    -2.844A    -1.537A
-1.15V    -736.4mA   -936mA     -381.5mA
-1.1V     -521.1mA   -682.5mA   -239.9mA
-1.05V    -339.8mA   -464.2mA   -135.4mA
-1V       -201.7mA   -289.9mA   -78.57mA
-950mV    -112.4mA   -165.7mA   -58.15mA
-900mV    -66.34mA   -90.7mA    -50.93mA
-850mV    -46.73mA   -53.1mA    -46.3mA
-750mV    -33.6mA    -29.18mA   -37.9mA
-350mV    -11.65mA   -9.73mA    -13.25mA
700mV     0A         0A         -269uA
2.9V      0A         0A         0A
[POWER_clamp]
|Voltage   I(typ)   I(min)   I(max)
-1.45V    2.199A     2.812A     1.214A
-1.2V     921.4mA    1.215A     461.7mA
-1.15V    701.6mA    938.3mA    332.7mA
-1.1V     503.3mA    687.8mA    219.8mA
-1.05V    334mA      471mA      132.2mA
-1V       202.3mA    296.3mA    80.35mA
-950mV    114.7mA    170.6mA    59.82mA
-900mV    68.02mA    93.72mA    52.22mA
-850mV    47.71mA    54.84mA    47.28mA
-750mV    33.99mA    30.1mA     38.29mA
700mV     0A         0A         321.5uA
2.9V      0A         0A         0A
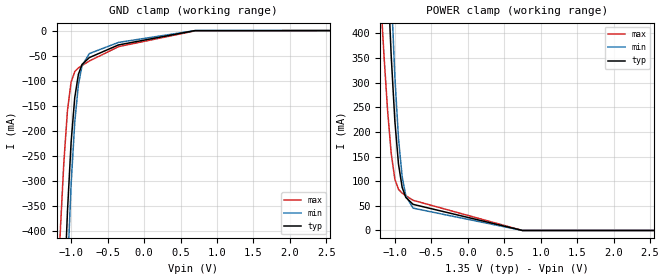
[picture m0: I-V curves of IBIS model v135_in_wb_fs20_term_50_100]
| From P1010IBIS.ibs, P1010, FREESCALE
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[Model]  v135_in_wb_fs20_term_50_100
|   Model v135_in_wb_fs20_term_50_100
| This model has derived from v135_wb_fs20_term_50_100
| Only applicable curves and parameters are copied
Model_type Input
Polarity   Non-Inverting
Enable   Active-High
Vinl =   0.5150V
Vinh =   0.9350V
C_comp   1.8966pF   1.6657pF   2.1891pF
[Receiver Thresholds]
Vth   =  0.675V
Vinh_ac  =  0.160V
Vinh_dc  =  0.090V
Vinl_ac  = -0.160V
Vinl_dc  = -0.090V
[Temperature Range]   65.0000   0.1050k   -40.0000
[Voltage Range]   1.3500V   1.2830V   1.4500V
[GND_clamp]
|Voltage   I(typ)   I(min)   I(max)
-1.45V    -2.411A    -2.86A     -1.562A
-1.15V    -758.2mA   -953.5mA   -406.4mA
-1.1V     -542.9mA   -700mA     -264.6mA
-1.05V    -361.5mA   -481.8mA   -159.8mA
-1V       -223.2mA   -307.4mA   -102.7mA
-950mV    -133.8mA   -183.2mA   -82.06mA
-900mV    -87.47mA   -108mA     -74.6mA
-850mV    -67.62mA   -70.23mA   -69.72mA
-750mV    -53.99mA   -45.93mA   -60.86mA
-350mV    -28.68mA   -23.64mA   -32.09mA
700mV     0A         0A         -571.1uA
2.9V      0A         0A         0A
[POWER_clamp]
|Voltage   I(typ)   I(min)   I(max)
-1.45V    2.218A     2.826A     1.239A
-1.2V     941.3mA    1.23A      486.3mA
-1.15V    721.5mA    954mA      357.2mA
-1.1V     523.3mA    703.6mA    244.1mA
-1.05V    354mA      486.8mA    156.3mA
-1V       222.1mA    312.1mA    104.2mA
-950mV    134.4mA    186.3mA    83.44mA
-900mV    87.57mA    109.3mA    75.65mA
-850mV    67.1mA     70.33mA    70.53mA
-750mV    53.01mA    45.29mA    61.24mA
750mV     0A         0A         0A
2.9V      0A         0A         0A
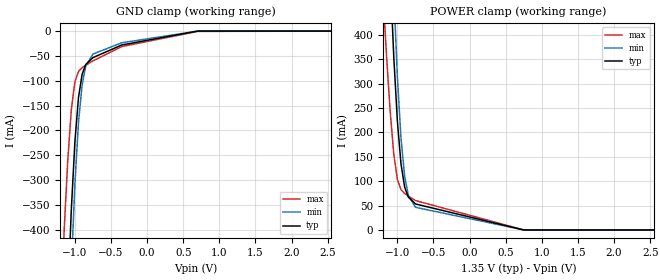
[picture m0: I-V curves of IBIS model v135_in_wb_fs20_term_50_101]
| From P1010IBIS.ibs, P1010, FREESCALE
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[Model]  v135_in_wb_fs20_term_50_101
|   Model v135_in_wb_fs20_term_50_101
| This model has derived from v135_wb_fs20_term_50_101
| Only applicable curves and parameters are copied
Model_type Input
Polarity   Non-Inverting
Enable   Active-High
Vinl =   0.5150V
Vinh =   0.9350V
C_comp   1.8437pF   1.6191pF   2.1421pF
[Receiver Thresholds]
Vth   =  0.675V
Vinh_ac  =  0.160V
Vinh_dc  =  0.090V
Vinl_ac  = -0.160V
Vinl_dc  = -0.090V
[Temperature Range]   65.0000   0.1050k   -40.0000
[Voltage Range]   1.3500V   1.2830V   1.4500V
[GND_clamp]
|Voltage   I(typ)   I(min)   I(max)
-1.45V    -2.412A    -2.862A    -1.562A
-1.15V    -758.4mA   -954.6mA   -405.7mA
-1.1V     -543mA     -701mA     -263.9mA
-1.05V    -361.5mA   -482.7mA   -159mA
-1V       -223.1mA   -308.1mA   -101.9mA
-950mV    -133.5mA   -183.8mA   -81.16mA
-900mV    -87.15mA   -108.5mA   -73.67mA
-850mV    -67.22mA   -70.66mA   -68.78mA
-750mV    -53.47mA   -46.2mA    -59.9mA
-350mV    -27.96mA   -23.49mA   -31.18mA
700mV     0A         0A         -601.8uA
2.9V      0A         0A         0A
[POWER_clamp]
|Voltage   I(typ)   I(min)   I(max)
-1.45V    2.22A      2.829A     1.239A
-1.2V     942.9mA    1.233A     485.9mA
-1.15V    723mA      956.1mA    356.7mA
-1.1V     524.6mA    705.6mA    243.5mA
-1.05V    355.1mA    488.7mA    155.7mA
-1V       223.1mA    313.9mA    103.5mA
-950mV    135.2mA    188mA      82.72mA
-900mV    88.27mA    110.8mA    74.88mA
-850mV    67.68mA    71.73mA    69.73mA
-750mV    53.41mA    46.49mA    60.4mA
750mV     0A         0A         0A
2.9V      0A         0A         0A
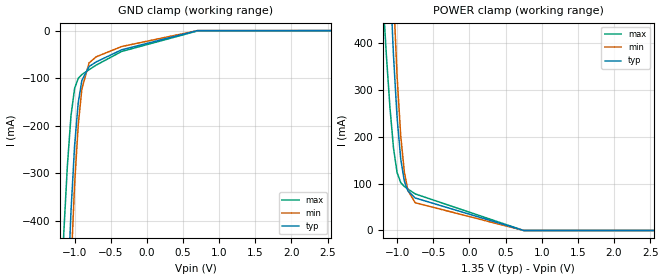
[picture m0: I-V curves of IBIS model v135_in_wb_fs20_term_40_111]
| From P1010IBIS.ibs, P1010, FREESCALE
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[Model]  v135_in_wb_fs20_term_40_111
|   Model v135_in_wb_fs20_term_40_111
| This model has derived from v135_wb_fs20_term_40_111
| Only applicable curves and parameters are copied
Model_type Input
Polarity   Non-Inverting
Enable   Active-High
Vinl =   0.5150V
Vinh =   0.9350V
C_comp   1.7854pF   1.5672pF   2.0817pF
[Receiver Thresholds]
Vth   =  0.675V
Vinh_ac  =  0.160V
Vinh_dc  =  0.090V
Vinl_ac  = -0.160V
Vinl_dc  = -0.090V
[Temperature Range]   65.0000   0.1050k   -40.0000
[Voltage Range]   1.3500V   1.2830V   1.4500V
[GND_clamp]
|Voltage   I(typ)   I(min)   I(max)
-1.45V    -2.433A    -2.878A    -1.584A
-1.15V    -777.7mA   -970.3mA   -426.3mA
-1.1V     -562.1mA   -716.5mA   -284.2mA
-1.05V    -380.2mA   -498mA     -178.9mA
-1V       -241.6mA   -323.3mA   -121.5mA
-950mV    -151.7mA   -198.7mA   -100.4mA
-900mV    -105mA     -123.1mA   -92.51mA
-800mV    -75.67mA   -67.91mA   -82.19mA
-700mV    -65.73mA   -55.03mA   -72.45mA
-350mV    -40.42mA   -33.6mA    -43.93mA
700mV     0A         0A         -786.7uA
2.9V      0A         0A         0A
[POWER_clamp]
|Voltage   I(typ)   I(min)   I(max)
-1.45V    2.239A     2.844A     1.261A
-1.2V     961mA      1.247A     506.8mA
-1.15V    740.9mA    970.5mA    377.3mA
-1.1V     542.4mA    719.8mA    263.8mA
-1.05V    372.6mA    502.7mA    175.7mA
-1V       240.4mA    327.7mA    123.2mA
-950mV    152.3mA    201.6mA    102.1mA
-900mV    105.1mA    124.3mA    93.84mA
-850mV    84.22mA    84.93mA    88.26mA
-750mV    69.27mA    59.16mA    77.91mA
750mV     0A         0A         0A
2.9V      0A         0A         0A
